VERSION 5.8 ;
DIVIDERCHAR "/" ;
BUSBITCHARS "[]" ;

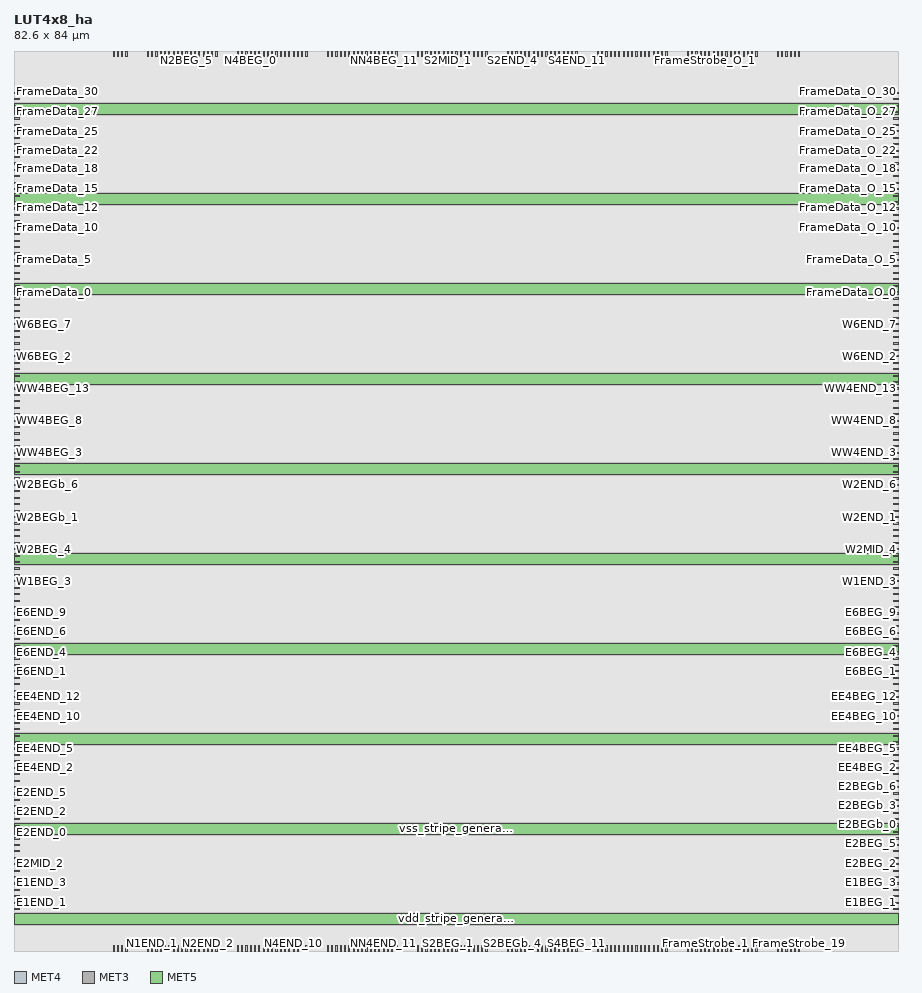
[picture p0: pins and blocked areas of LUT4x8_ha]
MACRO LUT4x8_ha
  CLASS BLOCK ;
  FOREIGN LUT4x8_ha ;
  ORIGIN 0.0 0.0 ;
  SIZE 82.600 BY 84.000 ;
  SYMMETRY X Y ;
  PIN N_GBUF_BEG_0
    DIRECTION OUTPUT ;
    USE SIGNAL ;
    PORT
      LAYER MET4 ;
        RECT 9.250 83.450 9.350 84.000 ;
    END
  END N_GBUF_BEG_0
  PIN N_GBUF_BEG_1
    DIRECTION OUTPUT ;
    USE SIGNAL ;
    PORT
      LAYER MET4 ;
        RECT 9.650 83.450 9.750 84.000 ;
    END
  END N_GBUF_BEG_1
  PIN N_GBUF_BEG_2
    DIRECTION OUTPUT ;
    USE SIGNAL ;
    PORT
      LAYER MET4 ;
        RECT 10.050 83.450 10.150 84.000 ;
    END
  END N_GBUF_BEG_2
  PIN N_GBUF_BEG_3
    DIRECTION OUTPUT ;
    USE SIGNAL ;
    PORT
      LAYER MET4 ;
        RECT 10.450 83.450 10.550 84.000 ;
    END
  END N_GBUF_BEG_3
  PIN N1BEG_0
    DIRECTION OUTPUT ;
    USE SIGNAL ;
    PORT
      LAYER MET4 ;
        RECT 12.450 83.450 12.550 84.000 ;
    END
  END N1BEG_0
  PIN N1BEG_1
    DIRECTION OUTPUT ;
    USE SIGNAL ;
    PORT
      LAYER MET4 ;
        RECT 12.850 83.450 12.950 84.000 ;
    END
  END N1BEG_1
  PIN N1BEG_2
    DIRECTION OUTPUT ;
    USE SIGNAL ;
    PORT
      LAYER MET4 ;
        RECT 13.250 83.450 13.350 84.000 ;
    END
  END N1BEG_2
  PIN N1BEG_3
    DIRECTION OUTPUT ;
    USE SIGNAL ;
    PORT
      LAYER MET4 ;
        RECT 13.650 83.450 13.750 84.000 ;
    END
  END N1BEG_3
  PIN N2BEG_0
    DIRECTION OUTPUT ;
    USE SIGNAL ;
    PORT
      LAYER MET4 ;
        RECT 14.050 83.450 14.150 84.000 ;
    END
  END N2BEG_0
  PIN N2BEG_1
    DIRECTION OUTPUT ;
    USE SIGNAL ;
    PORT
      LAYER MET4 ;
        RECT 14.450 83.450 14.550 84.000 ;
    END
  END N2BEG_1
  PIN N2BEG_2
    DIRECTION OUTPUT ;
    USE SIGNAL ;
    PORT
      LAYER MET4 ;
        RECT 14.850 83.450 14.950 84.000 ;
    END
  END N2BEG_2
  PIN N2BEG_3
    DIRECTION OUTPUT ;
    USE SIGNAL ;
    PORT
      LAYER MET4 ;
        RECT 15.250 83.450 15.350 84.000 ;
    END
  END N2BEG_3
  PIN N2BEG_4
    DIRECTION OUTPUT ;
    USE SIGNAL ;
    PORT
      LAYER MET4 ;
        RECT 15.650 83.450 15.750 84.000 ;
    END
  END N2BEG_4
  PIN N2BEG_5
    DIRECTION OUTPUT ;
    USE SIGNAL ;
    PORT
      LAYER MET4 ;
        RECT 16.050 83.450 16.150 84.000 ;
    END
  END N2BEG_5
  PIN N2BEG_6
    DIRECTION OUTPUT ;
    USE SIGNAL ;
    PORT
      LAYER MET4 ;
        RECT 16.450 83.450 16.550 84.000 ;
    END
  END N2BEG_6
  PIN N2BEG_7
    DIRECTION OUTPUT ;
    USE SIGNAL ;
    PORT
      LAYER MET4 ;
        RECT 16.850 83.450 16.950 84.000 ;
    END
  END N2BEG_7
  PIN N2BEGb_0
    DIRECTION OUTPUT ;
    USE SIGNAL ;
    PORT
      LAYER MET4 ;
        RECT 17.250 83.450 17.350 84.000 ;
    END
  END N2BEGb_0
  PIN N2BEGb_1
    DIRECTION OUTPUT ;
    USE SIGNAL ;
    PORT
      LAYER MET4 ;
        RECT 17.650 83.450 17.750 84.000 ;
    END
  END N2BEGb_1
  PIN N2BEGb_2
    DIRECTION OUTPUT ;
    USE SIGNAL ;
    PORT
      LAYER MET4 ;
        RECT 18.050 83.450 18.150 84.000 ;
    END
  END N2BEGb_2
  PIN N2BEGb_3
    DIRECTION OUTPUT ;
    USE SIGNAL ;
    PORT
      LAYER MET4 ;
        RECT 18.450 83.450 18.550 84.000 ;
    END
  END N2BEGb_3
  PIN N2BEGb_4
    DIRECTION OUTPUT ;
    USE SIGNAL ;
    PORT
      LAYER MET4 ;
        RECT 18.850 83.450 18.950 84.000 ;
    END
  END N2BEGb_4
  PIN N2BEGb_5
    DIRECTION OUTPUT ;
    USE SIGNAL ;
    PORT
      LAYER MET4 ;
        RECT 20.850 83.450 20.950 84.000 ;
    END
  END N2BEGb_5
  PIN N2BEGb_6
    DIRECTION OUTPUT ;
    USE SIGNAL ;
    PORT
      LAYER MET4 ;
        RECT 21.250 83.450 21.350 84.000 ;
    END
  END N2BEGb_6
  PIN N2BEGb_7
    DIRECTION OUTPUT ;
    USE SIGNAL ;
    PORT
      LAYER MET4 ;
        RECT 21.650 83.450 21.750 84.000 ;
    END
  END N2BEGb_7
  PIN N4BEG_0
    DIRECTION OUTPUT ;
    USE SIGNAL ;
    PORT
      LAYER MET4 ;
        RECT 22.050 83.450 22.150 84.000 ;
    END
  END N4BEG_0
  PIN N4BEG_1
    DIRECTION OUTPUT ;
    USE SIGNAL ;
    PORT
      LAYER MET4 ;
        RECT 22.450 83.450 22.550 84.000 ;
    END
  END N4BEG_1
  PIN N4BEG_2
    DIRECTION OUTPUT ;
    USE SIGNAL ;
    PORT
      LAYER MET4 ;
        RECT 22.850 83.450 22.950 84.000 ;
    END
  END N4BEG_2
  PIN N4BEG_3
    DIRECTION OUTPUT ;
    USE SIGNAL ;
    PORT
      LAYER MET4 ;
        RECT 23.250 83.450 23.350 84.000 ;
    END
  END N4BEG_3
  PIN N4BEG_4
    DIRECTION OUTPUT ;
    USE SIGNAL ;
    PORT
      LAYER MET4 ;
        RECT 23.650 83.450 23.750 84.000 ;
    END
  END N4BEG_4
  PIN N4BEG_5
    DIRECTION OUTPUT ;
    USE SIGNAL ;
    PORT
      LAYER MET4 ;
        RECT 24.050 83.450 24.150 84.000 ;
    END
  END N4BEG_5
  PIN N4BEG_6
    DIRECTION OUTPUT ;
    USE SIGNAL ;
    PORT
      LAYER MET4 ;
        RECT 24.450 83.450 24.550 84.000 ;
    END
  END N4BEG_6
  PIN N4BEG_7
    DIRECTION OUTPUT ;
    USE SIGNAL ;
    PORT
      LAYER MET4 ;
        RECT 24.850 83.450 24.950 84.000 ;
    END
  END N4BEG_7
  PIN N4BEG_8
    DIRECTION OUTPUT ;
    USE SIGNAL ;
    PORT
      LAYER MET4 ;
        RECT 25.250 83.450 25.350 84.000 ;
    END
  END N4BEG_8
  PIN N4BEG_9
    DIRECTION OUTPUT ;
    USE SIGNAL ;
    PORT
      LAYER MET4 ;
        RECT 25.650 83.450 25.750 84.000 ;
    END
  END N4BEG_9
  PIN N4BEG_10
    DIRECTION OUTPUT ;
    USE SIGNAL ;
    PORT
      LAYER MET4 ;
        RECT 26.050 83.450 26.150 84.000 ;
    END
  END N4BEG_10
  PIN N4BEG_11
    DIRECTION OUTPUT ;
    USE SIGNAL ;
    PORT
      LAYER MET4 ;
        RECT 26.450 83.450 26.550 84.000 ;
    END
  END N4BEG_11
  PIN N4BEG_12
    DIRECTION OUTPUT ;
    USE SIGNAL ;
    PORT
      LAYER MET4 ;
        RECT 26.850 83.450 26.950 84.000 ;
    END
  END N4BEG_12
  PIN N4BEG_13
    DIRECTION OUTPUT ;
    USE SIGNAL ;
    PORT
      LAYER MET4 ;
        RECT 27.250 83.450 27.350 84.000 ;
    END
  END N4BEG_13
  PIN N4BEG_14
    DIRECTION OUTPUT ;
    USE SIGNAL ;
    PORT
      LAYER MET4 ;
        RECT 29.250 83.450 29.350 84.000 ;
    END
  END N4BEG_14
  PIN N4BEG_15
    DIRECTION OUTPUT ;
    USE SIGNAL ;
    PORT
      LAYER MET4 ;
        RECT 29.650 83.450 29.750 84.000 ;
    END
  END N4BEG_15
  PIN NN4BEG_0
    DIRECTION OUTPUT ;
    USE SIGNAL ;
    PORT
      LAYER MET4 ;
        RECT 30.050 83.450 30.150 84.000 ;
    END
  END NN4BEG_0
  PIN NN4BEG_1
    DIRECTION OUTPUT ;
    USE SIGNAL ;
    PORT
      LAYER MET4 ;
        RECT 30.450 83.450 30.550 84.000 ;
    END
  END NN4BEG_1
  PIN NN4BEG_2
    DIRECTION OUTPUT ;
    USE SIGNAL ;
    PORT
      LAYER MET4 ;
        RECT 30.850 83.450 30.950 84.000 ;
    END
  END NN4BEG_2
  PIN NN4BEG_3
    DIRECTION OUTPUT ;
    USE SIGNAL ;
    PORT
      LAYER MET4 ;
        RECT 31.250 83.450 31.350 84.000 ;
    END
  END NN4BEG_3
  PIN NN4BEG_4
    DIRECTION OUTPUT ;
    USE SIGNAL ;
    PORT
      LAYER MET4 ;
        RECT 31.650 83.450 31.750 84.000 ;
    END
  END NN4BEG_4
  PIN NN4BEG_5
    DIRECTION OUTPUT ;
    USE SIGNAL ;
    PORT
      LAYER MET4 ;
        RECT 32.050 83.450 32.150 84.000 ;
    END
  END NN4BEG_5
  PIN NN4BEG_6
    DIRECTION OUTPUT ;
    USE SIGNAL ;
    PORT
      LAYER MET4 ;
        RECT 32.450 83.450 32.550 84.000 ;
    END
  END NN4BEG_6
  PIN NN4BEG_7
    DIRECTION OUTPUT ;
    USE SIGNAL ;
    PORT
      LAYER MET4 ;
        RECT 32.850 83.450 32.950 84.000 ;
    END
  END NN4BEG_7
  PIN NN4BEG_8
    DIRECTION OUTPUT ;
    USE SIGNAL ;
    PORT
      LAYER MET4 ;
        RECT 33.250 83.450 33.350 84.000 ;
    END
  END NN4BEG_8
  PIN NN4BEG_9
    DIRECTION OUTPUT ;
    USE SIGNAL ;
    PORT
      LAYER MET4 ;
        RECT 33.650 83.450 33.750 84.000 ;
    END
  END NN4BEG_9
  PIN NN4BEG_10
    DIRECTION OUTPUT ;
    USE SIGNAL ;
    PORT
      LAYER MET4 ;
        RECT 34.050 83.450 34.150 84.000 ;
    END
  END NN4BEG_10
  PIN NN4BEG_11
    DIRECTION OUTPUT ;
    USE SIGNAL ;
    PORT
      LAYER MET4 ;
        RECT 34.450 83.450 34.550 84.000 ;
    END
  END NN4BEG_11
  PIN NN4BEG_12
    DIRECTION OUTPUT ;
    USE SIGNAL ;
    PORT
      LAYER MET4 ;
        RECT 34.850 83.450 34.950 84.000 ;
    END
  END NN4BEG_12
  PIN NN4BEG_13
    DIRECTION OUTPUT ;
    USE SIGNAL ;
    PORT
      LAYER MET4 ;
        RECT 35.250 83.450 35.350 84.000 ;
    END
  END NN4BEG_13
  PIN NN4BEG_14
    DIRECTION OUTPUT ;
    USE SIGNAL ;
    PORT
      LAYER MET4 ;
        RECT 35.650 83.450 35.750 84.000 ;
    END
  END NN4BEG_14
  PIN NN4BEG_15
    DIRECTION OUTPUT ;
    USE SIGNAL ;
    PORT
      LAYER MET4 ;
        RECT 37.650 83.450 37.750 84.000 ;
    END
  END NN4BEG_15
  PIN S1END_0
    DIRECTION INPUT ;
    USE SIGNAL ;
    PORT
      LAYER MET4 ;
        RECT 38.450 83.450 38.550 84.000 ;
    END
  END S1END_0
  PIN S1END_1
    DIRECTION INPUT ;
    USE SIGNAL ;
    PORT
      LAYER MET4 ;
        RECT 38.850 83.450 38.950 84.000 ;
    END
  END S1END_1
  PIN S1END_2
    DIRECTION INPUT ;
    USE SIGNAL ;
    PORT
      LAYER MET4 ;
        RECT 39.250 83.450 39.350 84.000 ;
    END
  END S1END_2
  PIN S1END_3
    DIRECTION INPUT ;
    USE SIGNAL ;
    PORT
      LAYER MET4 ;
        RECT 39.650 83.450 39.750 84.000 ;
    END
  END S1END_3
  PIN S2MID_0
    DIRECTION INPUT ;
    USE SIGNAL ;
    PORT
      LAYER MET4 ;
        RECT 40.050 83.450 40.150 84.000 ;
    END
  END S2MID_0
  PIN S2MID_1
    DIRECTION INPUT ;
    USE SIGNAL ;
    PORT
      LAYER MET4 ;
        RECT 40.450 83.450 40.550 84.000 ;
    END
  END S2MID_1
  PIN S2MID_2
    DIRECTION INPUT ;
    USE SIGNAL ;
    PORT
      LAYER MET4 ;
        RECT 40.850 83.450 40.950 84.000 ;
    END
  END S2MID_2
  PIN S2MID_3
    DIRECTION INPUT ;
    USE SIGNAL ;
    PORT
      LAYER MET4 ;
        RECT 41.250 83.450 41.350 84.000 ;
    END
  END S2MID_3
  PIN S2MID_4
    DIRECTION INPUT ;
    USE SIGNAL ;
    PORT
      LAYER MET4 ;
        RECT 41.650 83.450 41.750 84.000 ;
    END
  END S2MID_4
  PIN S2MID_5
    DIRECTION INPUT ;
    USE SIGNAL ;
    PORT
      LAYER MET4 ;
        RECT 42.050 83.450 42.150 84.000 ;
    END
  END S2MID_5
  PIN S2MID_6
    DIRECTION INPUT ;
    USE SIGNAL ;
    PORT
      LAYER MET4 ;
        RECT 42.450 83.450 42.550 84.000 ;
    END
  END S2MID_6
  PIN S2MID_7
    DIRECTION INPUT ;
    USE SIGNAL ;
    PORT
      LAYER MET4 ;
        RECT 42.850 83.450 42.950 84.000 ;
    END
  END S2MID_7
  PIN S2END_0
    DIRECTION INPUT ;
    USE SIGNAL ;
    PORT
      LAYER MET4 ;
        RECT 43.250 83.450 43.350 84.000 ;
    END
  END S2END_0
  PIN S2END_1
    DIRECTION INPUT ;
    USE SIGNAL ;
    PORT
      LAYER MET4 ;
        RECT 43.650 83.450 43.750 84.000 ;
    END
  END S2END_1
  PIN S2END_2
    DIRECTION INPUT ;
    USE SIGNAL ;
    PORT
      LAYER MET4 ;
        RECT 44.050 83.450 44.150 84.000 ;
    END
  END S2END_2
  PIN S2END_3
    DIRECTION INPUT ;
    USE SIGNAL ;
    PORT
      LAYER MET4 ;
        RECT 46.050 83.450 46.150 84.000 ;
    END
  END S2END_3
  PIN S2END_4
    DIRECTION INPUT ;
    USE SIGNAL ;
    PORT
      LAYER MET4 ;
        RECT 46.450 83.450 46.550 84.000 ;
    END
  END S2END_4
  PIN S2END_5
    DIRECTION INPUT ;
    USE SIGNAL ;
    PORT
      LAYER MET4 ;
        RECT 46.850 83.450 46.950 84.000 ;
    END
  END S2END_5
  PIN S2END_6
    DIRECTION INPUT ;
    USE SIGNAL ;
    PORT
      LAYER MET4 ;
        RECT 47.250 83.450 47.350 84.000 ;
    END
  END S2END_6
  PIN S2END_7
    DIRECTION INPUT ;
    USE SIGNAL ;
    PORT
      LAYER MET4 ;
        RECT 47.650 83.450 47.750 84.000 ;
    END
  END S2END_7
  PIN S4END_0
    DIRECTION INPUT ;
    USE SIGNAL ;
    PORT
      LAYER MET4 ;
        RECT 48.050 83.450 48.150 84.000 ;
    END
  END S4END_0
  PIN S4END_1
    DIRECTION INPUT ;
    USE SIGNAL ;
    PORT
      LAYER MET4 ;
        RECT 48.450 83.450 48.550 84.000 ;
    END
  END S4END_1
  PIN S4END_2
    DIRECTION INPUT ;
    USE SIGNAL ;
    PORT
      LAYER MET4 ;
        RECT 48.850 83.450 48.950 84.000 ;
    END
  END S4END_2
  PIN S4END_3
    DIRECTION INPUT ;
    USE SIGNAL ;
    PORT
      LAYER MET4 ;
        RECT 49.250 83.450 49.350 84.000 ;
    END
  END S4END_3
  PIN S4END_4
    DIRECTION INPUT ;
    USE SIGNAL ;
    PORT
      LAYER MET4 ;
        RECT 49.650 83.450 49.750 84.000 ;
    END
  END S4END_4
  PIN S4END_5
    DIRECTION INPUT ;
    USE SIGNAL ;
    PORT
      LAYER MET4 ;
        RECT 50.050 83.450 50.150 84.000 ;
    END
  END S4END_5
  PIN S4END_6
    DIRECTION INPUT ;
    USE SIGNAL ;
    PORT
      LAYER MET4 ;
        RECT 50.450 83.450 50.550 84.000 ;
    END
  END S4END_6
  PIN S4END_7
    DIRECTION INPUT ;
    USE SIGNAL ;
    PORT
      LAYER MET4 ;
        RECT 50.850 83.450 50.950 84.000 ;
    END
  END S4END_7
  PIN S4END_8
    DIRECTION INPUT ;
    USE SIGNAL ;
    PORT
      LAYER MET4 ;
        RECT 51.250 83.450 51.350 84.000 ;
    END
  END S4END_8
  PIN S4END_9
    DIRECTION INPUT ;
    USE SIGNAL ;
    PORT
      LAYER MET4 ;
        RECT 51.650 83.450 51.750 84.000 ;
    END
  END S4END_9
  PIN S4END_10
    DIRECTION INPUT ;
    USE SIGNAL ;
    PORT
      LAYER MET4 ;
        RECT 52.050 83.450 52.150 84.000 ;
    END
  END S4END_10
  PIN S4END_11
    DIRECTION INPUT ;
    USE SIGNAL ;
    PORT
      LAYER MET4 ;
        RECT 52.450 83.450 52.550 84.000 ;
    END
  END S4END_11
  PIN S4END_12
    DIRECTION INPUT ;
    USE SIGNAL ;
    PORT
      LAYER MET4 ;
        RECT 54.450 83.450 54.550 84.000 ;
    END
  END S4END_12
  PIN S4END_13
    DIRECTION INPUT ;
    USE SIGNAL ;
    PORT
      LAYER MET4 ;
        RECT 54.850 83.450 54.950 84.000 ;
    END
  END S4END_13
  PIN S4END_14
    DIRECTION INPUT ;
    USE SIGNAL ;
    PORT
      LAYER MET4 ;
        RECT 55.250 83.450 55.350 84.000 ;
    END
  END S4END_14
  PIN S4END_15
    DIRECTION INPUT ;
    USE SIGNAL ;
    PORT
      LAYER MET4 ;
        RECT 55.650 83.450 55.750 84.000 ;
    END
  END S4END_15
  PIN SS4END_0
    DIRECTION INPUT ;
    USE SIGNAL ;
    PORT
      LAYER MET4 ;
        RECT 56.050 83.450 56.150 84.000 ;
    END
  END SS4END_0
  PIN SS4END_1
    DIRECTION INPUT ;
    USE SIGNAL ;
    PORT
      LAYER MET4 ;
        RECT 56.450 83.450 56.550 84.000 ;
    END
  END SS4END_1
  PIN SS4END_2
    DIRECTION INPUT ;
    USE SIGNAL ;
    PORT
      LAYER MET4 ;
        RECT 56.850 83.450 56.950 84.000 ;
    END
  END SS4END_2
  PIN SS4END_3
    DIRECTION INPUT ;
    USE SIGNAL ;
    PORT
      LAYER MET4 ;
        RECT 57.250 83.450 57.350 84.000 ;
    END
  END SS4END_3
  PIN SS4END_4
    DIRECTION INPUT ;
    USE SIGNAL ;
    PORT
      LAYER MET4 ;
        RECT 57.650 83.450 57.750 84.000 ;
    END
  END SS4END_4
  PIN SS4END_5
    DIRECTION INPUT ;
    USE SIGNAL ;
    PORT
      LAYER MET4 ;
        RECT 58.050 83.450 58.150 84.000 ;
    END
  END SS4END_5
  PIN SS4END_6
    DIRECTION INPUT ;
    USE SIGNAL ;
    PORT
      LAYER MET4 ;
        RECT 58.450 83.450 58.550 84.000 ;
    END
  END SS4END_6
  PIN SS4END_7
    DIRECTION INPUT ;
    USE SIGNAL ;
    PORT
      LAYER MET4 ;
        RECT 58.850 83.450 58.950 84.000 ;
    END
  END SS4END_7
  PIN SS4END_8
    DIRECTION INPUT ;
    USE SIGNAL ;
    PORT
      LAYER MET4 ;
        RECT 59.250 83.450 59.350 84.000 ;
    END
  END SS4END_8
  PIN SS4END_9
    DIRECTION INPUT ;
    USE SIGNAL ;
    PORT
      LAYER MET4 ;
        RECT 59.650 83.450 59.750 84.000 ;
    END
  END SS4END_9
  PIN SS4END_10
    DIRECTION INPUT ;
    USE SIGNAL ;
    PORT
      LAYER MET4 ;
        RECT 60.050 83.450 60.150 84.000 ;
    END
  END SS4END_10
  PIN SS4END_11
    DIRECTION INPUT ;
    USE SIGNAL ;
    PORT
      LAYER MET4 ;
        RECT 60.450 83.450 60.550 84.000 ;
    END
  END SS4END_11
  PIN SS4END_12
    DIRECTION INPUT ;
    USE SIGNAL ;
    PORT
      LAYER MET4 ;
        RECT 60.850 83.450 60.950 84.000 ;
    END
  END SS4END_12
  PIN SS4END_13
    DIRECTION INPUT ;
    USE SIGNAL ;
    PORT
      LAYER MET4 ;
        RECT 62.850 83.450 62.950 84.000 ;
    END
  END SS4END_13
  PIN SS4END_14
    DIRECTION INPUT ;
    USE SIGNAL ;
    PORT
      LAYER MET4 ;
        RECT 63.250 83.450 63.350 84.000 ;
    END
  END SS4END_14
  PIN SS4END_15
    DIRECTION INPUT ;
    USE SIGNAL ;
    PORT
      LAYER MET4 ;
        RECT 63.650 83.450 63.750 84.000 ;
    END
  END SS4END_15
  PIN CO_0
    DIRECTION OUTPUT ;
    USE SIGNAL ;
    PORT
      LAYER MET4 ;
        RECT 38.050 83.450 38.150 84.000 ;
    END
  END CO_0
  PIN E1BEG_0
    DIRECTION OUTPUT ;
    USE SIGNAL ;
    PORT
      LAYER MET3 ;
        RECT 82.050 3.850 82.600 3.950 ;
    END
  END E1BEG_0
  PIN E1BEG_1
    DIRECTION OUTPUT ;
    USE SIGNAL ;
    PORT
      LAYER MET3 ;
        RECT 82.050 4.450 82.600 4.550 ;
    END
  END E1BEG_1
  PIN E1BEG_2
    DIRECTION OUTPUT ;
    USE SIGNAL ;
    PORT
      LAYER MET3 ;
        RECT 82.050 5.050 82.600 5.150 ;
    END
  END E1BEG_2
  PIN E1BEG_3
    DIRECTION OUTPUT ;
    USE SIGNAL ;
    PORT
      LAYER MET3 ;
        RECT 82.050 5.650 82.600 5.750 ;
    END
  END E1BEG_3
  PIN E2BEG_0
    DIRECTION OUTPUT ;
    USE SIGNAL ;
    PORT
      LAYER MET3 ;
        RECT 82.050 6.250 82.600 6.350 ;
    END
  END E2BEG_0
  PIN E2BEG_1
    DIRECTION OUTPUT ;
    USE SIGNAL ;
    PORT
      LAYER MET3 ;
        RECT 82.050 6.850 82.600 6.950 ;
    END
  END E2BEG_1
  PIN E2BEG_2
    DIRECTION OUTPUT ;
    USE SIGNAL ;
    PORT
      LAYER MET3 ;
        RECT 82.050 7.450 82.600 7.550 ;
    END
  END E2BEG_2
  PIN E2BEG_3
    DIRECTION OUTPUT ;
    USE SIGNAL ;
    PORT
      LAYER MET3 ;
        RECT 82.050 8.050 82.600 8.150 ;
    END
  END E2BEG_3
  PIN E2BEG_4
    DIRECTION OUTPUT ;
    USE SIGNAL ;
    PORT
      LAYER MET3 ;
        RECT 82.050 8.650 82.600 8.750 ;
    END
  END E2BEG_4
  PIN E2BEG_5
    DIRECTION OUTPUT ;
    USE SIGNAL ;
    PORT
      LAYER MET3 ;
        RECT 82.050 9.250 82.600 9.350 ;
    END
  END E2BEG_5
  PIN E2BEG_6
    DIRECTION OUTPUT ;
    USE SIGNAL ;
    PORT
      LAYER MET3 ;
        RECT 82.050 9.850 82.600 9.950 ;
    END
  END E2BEG_6
  PIN E2BEG_7
    DIRECTION OUTPUT ;
    USE SIGNAL ;
    PORT
      LAYER MET3 ;
        RECT 82.050 10.450 82.600 10.550 ;
    END
  END E2BEG_7
  PIN E2BEGb_0
    DIRECTION OUTPUT ;
    USE SIGNAL ;
    PORT
      LAYER MET3 ;
        RECT 82.050 11.050 82.600 11.150 ;
    END
  END E2BEGb_0
  PIN E2BEGb_1
    DIRECTION OUTPUT ;
    USE SIGNAL ;
    PORT
      LAYER MET3 ;
        RECT 82.050 11.650 82.600 11.750 ;
    END
  END E2BEGb_1
  PIN E2BEGb_2
    DIRECTION OUTPUT ;
    USE SIGNAL ;
    PORT
      LAYER MET3 ;
        RECT 82.050 12.250 82.600 12.350 ;
    END
  END E2BEGb_2
  PIN E2BEGb_3
    DIRECTION OUTPUT ;
    USE SIGNAL ;
    PORT
      LAYER MET3 ;
        RECT 82.050 12.850 82.600 12.950 ;
    END
  END E2BEGb_3
  PIN E2BEGb_4
    DIRECTION OUTPUT ;
    USE SIGNAL ;
    PORT
      LAYER MET3 ;
        RECT 82.050 13.450 82.600 13.550 ;
    END
  END E2BEGb_4
  PIN E2BEGb_5
    DIRECTION OUTPUT ;
    USE SIGNAL ;
    PORT
      LAYER MET3 ;
        RECT 82.050 14.050 82.600 14.150 ;
    END
  END E2BEGb_5
  PIN E2BEGb_6
    DIRECTION OUTPUT ;
    USE SIGNAL ;
    PORT
      LAYER MET3 ;
        RECT 82.050 14.650 82.600 14.750 ;
    END
  END E2BEGb_6
  PIN E2BEGb_7
    DIRECTION OUTPUT ;
    USE SIGNAL ;
    PORT
      LAYER MET3 ;
        RECT 82.050 15.250 82.600 15.350 ;
    END
  END E2BEGb_7
  PIN EE4BEG_0
    DIRECTION OUTPUT ;
    USE SIGNAL ;
    PORT
      LAYER MET3 ;
        RECT 82.050 15.850 82.600 15.950 ;
    END
  END EE4BEG_0
  PIN EE4BEG_1
    DIRECTION OUTPUT ;
    USE SIGNAL ;
    PORT
      LAYER MET3 ;
        RECT 82.050 16.450 82.600 16.550 ;
    END
  END EE4BEG_1
  PIN EE4BEG_2
    DIRECTION OUTPUT ;
    USE SIGNAL ;
    PORT
      LAYER MET3 ;
        RECT 82.050 17.050 82.600 17.150 ;
    END
  END EE4BEG_2
  PIN EE4BEG_3
    DIRECTION OUTPUT ;
    USE SIGNAL ;
    PORT
      LAYER MET3 ;
        RECT 82.050 17.650 82.600 17.750 ;
    END
  END EE4BEG_3
  PIN EE4BEG_4
    DIRECTION OUTPUT ;
    USE SIGNAL ;
    PORT
      LAYER MET3 ;
        RECT 82.050 18.250 82.600 18.350 ;
    END
  END EE4BEG_4
  PIN EE4BEG_5
    DIRECTION OUTPUT ;
    USE SIGNAL ;
    PORT
      LAYER MET3 ;
        RECT 82.050 18.850 82.600 18.950 ;
    END
  END EE4BEG_5
  PIN EE4BEG_6
    DIRECTION OUTPUT ;
    USE SIGNAL ;
    PORT
      LAYER MET3 ;
        RECT 82.050 19.450 82.600 19.550 ;
    END
  END EE4BEG_6
  PIN EE4BEG_7
    DIRECTION OUTPUT ;
    USE SIGNAL ;
    PORT
      LAYER MET3 ;
        RECT 82.050 20.050 82.600 20.150 ;
    END
  END EE4BEG_7
  PIN EE4BEG_8
    DIRECTION OUTPUT ;
    USE SIGNAL ;
    PORT
      LAYER MET3 ;
        RECT 82.050 20.650 82.600 20.750 ;
    END
  END EE4BEG_8
  PIN EE4BEG_9
    DIRECTION OUTPUT ;
    USE SIGNAL ;
    PORT
      LAYER MET3 ;
        RECT 82.050 21.250 82.600 21.350 ;
    END
  END EE4BEG_9
  PIN EE4BEG_10
    DIRECTION OUTPUT ;
    USE SIGNAL ;
    PORT
      LAYER MET3 ;
        RECT 82.050 21.850 82.600 21.950 ;
    END
  END EE4BEG_10
  PIN EE4BEG_11
    DIRECTION OUTPUT ;
    USE SIGNAL ;
    PORT
      LAYER MET3 ;
        RECT 82.050 22.450 82.600 22.550 ;
    END
  END EE4BEG_11
  PIN EE4BEG_12
    DIRECTION OUTPUT ;
    USE SIGNAL ;
    PORT
      LAYER MET3 ;
        RECT 82.050 23.050 82.600 23.150 ;
    END
  END EE4BEG_12
  PIN EE4BEG_13
    DIRECTION OUTPUT ;
    USE SIGNAL ;
    PORT
      LAYER MET3 ;
        RECT 82.050 23.650 82.600 23.750 ;
    END
  END EE4BEG_13
  PIN EE4BEG_14
    DIRECTION OUTPUT ;
    USE SIGNAL ;
    PORT
      LAYER MET3 ;
        RECT 82.050 24.250 82.600 24.350 ;
    END
  END EE4BEG_14
  PIN EE4BEG_15
    DIRECTION OUTPUT ;
    USE SIGNAL ;
    PORT
      LAYER MET3 ;
        RECT 82.050 24.850 82.600 24.950 ;
    END
  END EE4BEG_15
  PIN E6BEG_0
    DIRECTION OUTPUT ;
    USE SIGNAL ;
    PORT
      LAYER MET3 ;
        RECT 82.050 25.450 82.600 25.550 ;
    END
  END E6BEG_0
  PIN E6BEG_1
    DIRECTION OUTPUT ;
    USE SIGNAL ;
    PORT
      LAYER MET3 ;
        RECT 82.050 26.050 82.600 26.150 ;
    END
  END E6BEG_1
  PIN E6BEG_2
    DIRECTION OUTPUT ;
    USE SIGNAL ;
    PORT
      LAYER MET3 ;
        RECT 82.050 26.650 82.600 26.750 ;
    END
  END E6BEG_2
  PIN E6BEG_3
    DIRECTION OUTPUT ;
    USE SIGNAL ;
    PORT
      LAYER MET3 ;
        RECT 82.050 27.250 82.600 27.350 ;
    END
  END E6BEG_3
  PIN E6BEG_4
    DIRECTION OUTPUT ;
    USE SIGNAL ;
    PORT
      LAYER MET3 ;
        RECT 82.050 27.850 82.600 27.950 ;
    END
  END E6BEG_4
  PIN E6BEG_5
    DIRECTION OUTPUT ;
    USE SIGNAL ;
    PORT
      LAYER MET3 ;
        RECT 82.050 28.450 82.600 28.550 ;
    END
  END E6BEG_5
  PIN E6BEG_6
    DIRECTION OUTPUT ;
    USE SIGNAL ;
    PORT
      LAYER MET3 ;
        RECT 82.050 29.050 82.600 29.150 ;
    END
  END E6BEG_6
  PIN E6BEG_7
    DIRECTION OUTPUT ;
    USE SIGNAL ;
    PORT
      LAYER MET3 ;
        RECT 82.050 29.650 82.600 29.750 ;
    END
  END E6BEG_7
  PIN E6BEG_8
    DIRECTION OUTPUT ;
    USE SIGNAL ;
    PORT
      LAYER MET3 ;
        RECT 82.050 30.250 82.600 30.350 ;
    END
  END E6BEG_8
  PIN E6BEG_9
    DIRECTION OUTPUT ;
    USE SIGNAL ;
    PORT
      LAYER MET3 ;
        RECT 82.050 30.850 82.600 30.950 ;
    END
  END E6BEG_9
  PIN E6BEG_10
    DIRECTION OUTPUT ;
    USE SIGNAL ;
    PORT
      LAYER MET3 ;
        RECT 82.050 31.450 82.600 31.550 ;
    END
  END E6BEG_10
  PIN E6BEG_11
    DIRECTION OUTPUT ;
    USE SIGNAL ;
    PORT
      LAYER MET3 ;
        RECT 82.050 32.050 82.600 32.150 ;
    END
  END E6BEG_11
  PIN W1END_0
    DIRECTION INPUT ;
    USE SIGNAL ;
    PORT
      LAYER MET3 ;
        RECT 82.050 32.650 82.600 32.750 ;
    END
  END W1END_0
  PIN W1END_1
    DIRECTION INPUT ;
    USE SIGNAL ;
    PORT
      LAYER MET3 ;
        RECT 82.050 33.250 82.600 33.350 ;
    END
  END W1END_1
  PIN W1END_2
    DIRECTION INPUT ;
    USE SIGNAL ;
    PORT
      LAYER MET3 ;
        RECT 82.050 33.850 82.600 33.950 ;
    END
  END W1END_2
  PIN W1END_3
    DIRECTION INPUT ;
    USE SIGNAL ;
    PORT
      LAYER MET3 ;
        RECT 82.050 34.450 82.600 34.550 ;
    END
  END W1END_3
  PIN W2MID_0
    DIRECTION INPUT ;
    USE SIGNAL ;
    PORT
      LAYER MET3 ;
        RECT 82.050 35.050 82.600 35.150 ;
    END
  END W2MID_0
  PIN W2MID_1
    DIRECTION INPUT ;
    USE SIGNAL ;
    PORT
      LAYER MET3 ;
        RECT 82.050 35.650 82.600 35.750 ;
    END
  END W2MID_1
  PIN W2MID_2
    DIRECTION INPUT ;
    USE SIGNAL ;
    PORT
      LAYER MET3 ;
        RECT 82.050 36.250 82.600 36.350 ;
    END
  END W2MID_2
  PIN W2MID_3
    DIRECTION INPUT ;
    USE SIGNAL ;
    PORT
      LAYER MET3 ;
        RECT 82.050 36.850 82.600 36.950 ;
    END
  END W2MID_3
  PIN W2MID_4
    DIRECTION INPUT ;
    USE SIGNAL ;
    PORT
      LAYER MET3 ;
        RECT 82.050 37.450 82.600 37.550 ;
    END
  END W2MID_4
  PIN W2MID_5
    DIRECTION INPUT ;
    USE SIGNAL ;
    PORT
      LAYER MET3 ;
        RECT 82.050 38.050 82.600 38.150 ;
    END
  END W2MID_5
  PIN W2MID_6
    DIRECTION INPUT ;
    USE SIGNAL ;
    PORT
      LAYER MET3 ;
        RECT 82.050 38.650 82.600 38.750 ;
    END
  END W2MID_6
  PIN W2MID_7
    DIRECTION INPUT ;
    USE SIGNAL ;
    PORT
      LAYER MET3 ;
        RECT 82.050 39.250 82.600 39.350 ;
    END
  END W2MID_7
  PIN W2END_0
    DIRECTION INPUT ;
    USE SIGNAL ;
    PORT
      LAYER MET3 ;
        RECT 82.050 39.850 82.600 39.950 ;
    END
  END W2END_0
  PIN W2END_1
    DIRECTION INPUT ;
    USE SIGNAL ;
    PORT
      LAYER MET3 ;
        RECT 82.050 40.450 82.600 40.550 ;
    END
  END W2END_1
  PIN W2END_2
    DIRECTION INPUT ;
    USE SIGNAL ;
    PORT
      LAYER MET3 ;
        RECT 82.050 41.050 82.600 41.150 ;
    END
  END W2END_2
  PIN W2END_3
    DIRECTION INPUT ;
    USE SIGNAL ;
    PORT
      LAYER MET3 ;
        RECT 82.050 41.650 82.600 41.750 ;
    END
  END W2END_3
  PIN W2END_4
    DIRECTION INPUT ;
    USE SIGNAL ;
    PORT
      LAYER MET3 ;
        RECT 82.050 42.250 82.600 42.350 ;
    END
  END W2END_4
  PIN W2END_5
    DIRECTION INPUT ;
    USE SIGNAL ;
    PORT
      LAYER MET3 ;
        RECT 82.050 42.850 82.600 42.950 ;
    END
  END W2END_5
  PIN W2END_6
    DIRECTION INPUT ;
    USE SIGNAL ;
    PORT
      LAYER MET3 ;
        RECT 82.050 43.450 82.600 43.550 ;
    END
  END W2END_6
  PIN W2END_7
    DIRECTION INPUT ;
    USE SIGNAL ;
    PORT
      LAYER MET3 ;
        RECT 82.050 44.050 82.600 44.150 ;
    END
  END W2END_7
  PIN WW4END_0
    DIRECTION INPUT ;
    USE SIGNAL ;
    PORT
      LAYER MET3 ;
        RECT 82.050 44.650 82.600 44.750 ;
    END
  END WW4END_0
  PIN WW4END_1
    DIRECTION INPUT ;
    USE SIGNAL ;
    PORT
      LAYER MET3 ;
        RECT 82.050 45.250 82.600 45.350 ;
    END
  END WW4END_1
  PIN WW4END_2
    DIRECTION INPUT ;
    USE SIGNAL ;
    PORT
      LAYER MET3 ;
        RECT 82.050 45.850 82.600 45.950 ;
    END
  END WW4END_2
  PIN WW4END_3
    DIRECTION INPUT ;
    USE SIGNAL ;
    PORT
      LAYER MET3 ;
        RECT 82.050 46.450 82.600 46.550 ;
    END
  END WW4END_3
  PIN WW4END_4
    DIRECTION INPUT ;
    USE SIGNAL ;
    PORT
      LAYER MET3 ;
        RECT 82.050 47.050 82.600 47.150 ;
    END
  END WW4END_4
  PIN WW4END_5
    DIRECTION INPUT ;
    USE SIGNAL ;
    PORT
      LAYER MET3 ;
        RECT 82.050 47.650 82.600 47.750 ;
    END
  END WW4END_5
  PIN WW4END_6
    DIRECTION INPUT ;
    USE SIGNAL ;
    PORT
      LAYER MET3 ;
        RECT 82.050 48.250 82.600 48.350 ;
    END
  END WW4END_6
  PIN WW4END_7
    DIRECTION INPUT ;
    USE SIGNAL ;
    PORT
      LAYER MET3 ;
        RECT 82.050 48.850 82.600 48.950 ;
    END
  END WW4END_7
  PIN WW4END_8
    DIRECTION INPUT ;
    USE SIGNAL ;
    PORT
      LAYER MET3 ;
        RECT 82.050 49.450 82.600 49.550 ;
    END
  END WW4END_8
  PIN WW4END_9
    DIRECTION INPUT ;
    USE SIGNAL ;
    PORT
      LAYER MET3 ;
        RECT 82.050 50.050 82.600 50.150 ;
    END
  END WW4END_9
  PIN WW4END_10
    DIRECTION INPUT ;
    USE SIGNAL ;
    PORT
      LAYER MET3 ;
        RECT 82.050 50.650 82.600 50.750 ;
    END
  END WW4END_10
  PIN WW4END_11
    DIRECTION INPUT ;
    USE SIGNAL ;
    PORT
      LAYER MET3 ;
        RECT 82.050 51.250 82.600 51.350 ;
    END
  END WW4END_11
  PIN WW4END_12
    DIRECTION INPUT ;
    USE SIGNAL ;
    PORT
      LAYER MET3 ;
        RECT 82.050 51.850 82.600 51.950 ;
    END
  END WW4END_12
  PIN WW4END_13
    DIRECTION INPUT ;
    USE SIGNAL ;
    PORT
      LAYER MET3 ;
        RECT 82.050 52.450 82.600 52.550 ;
    END
  END WW4END_13
  PIN WW4END_14
    DIRECTION INPUT ;
    USE SIGNAL ;
    PORT
      LAYER MET3 ;
        RECT 82.050 53.050 82.600 53.150 ;
    END
  END WW4END_14
  PIN WW4END_15
    DIRECTION INPUT ;
    USE SIGNAL ;
    PORT
      LAYER MET3 ;
        RECT 82.050 53.650 82.600 53.750 ;
    END
  END WW4END_15
  PIN W6END_0
    DIRECTION INPUT ;
    USE SIGNAL ;
    PORT
      LAYER MET3 ;
        RECT 82.050 54.250 82.600 54.350 ;
    END
  END W6END_0
  PIN W6END_1
    DIRECTION INPUT ;
    USE SIGNAL ;
    PORT
      LAYER MET3 ;
        RECT 82.050 54.850 82.600 54.950 ;
    END
  END W6END_1
  PIN W6END_2
    DIRECTION INPUT ;
    USE SIGNAL ;
    PORT
      LAYER MET3 ;
        RECT 82.050 55.450 82.600 55.550 ;
    END
  END W6END_2
  PIN W6END_3
    DIRECTION INPUT ;
    USE SIGNAL ;
    PORT
      LAYER MET3 ;
        RECT 82.050 56.050 82.600 56.150 ;
    END
  END W6END_3
  PIN W6END_4
    DIRECTION INPUT ;
    USE SIGNAL ;
    PORT
      LAYER MET3 ;
        RECT 82.050 56.650 82.600 56.750 ;
    END
  END W6END_4
  PIN W6END_5
    DIRECTION INPUT ;
    USE SIGNAL ;
    PORT
      LAYER MET3 ;
        RECT 82.050 57.250 82.600 57.350 ;
    END
  END W6END_5
  PIN W6END_6
    DIRECTION INPUT ;
    USE SIGNAL ;
    PORT
      LAYER MET3 ;
        RECT 82.050 57.850 82.600 57.950 ;
    END
  END W6END_6
  PIN W6END_7
    DIRECTION INPUT ;
    USE SIGNAL ;
    PORT
      LAYER MET3 ;
        RECT 82.050 58.450 82.600 58.550 ;
    END
  END W6END_7
  PIN W6END_8
    DIRECTION INPUT ;
    USE SIGNAL ;
    PORT
      LAYER MET3 ;
        RECT 82.050 59.050 82.600 59.150 ;
    END
  END W6END_8
  PIN W6END_9
    DIRECTION INPUT ;
    USE SIGNAL ;
    PORT
      LAYER MET3 ;
        RECT 82.050 59.650 82.600 59.750 ;
    END
  END W6END_9
  PIN W6END_10
    DIRECTION INPUT ;
    USE SIGNAL ;
    PORT
      LAYER MET3 ;
        RECT 82.050 60.250 82.600 60.350 ;
    END
  END W6END_10
  PIN W6END_11
    DIRECTION INPUT ;
    USE SIGNAL ;
    PORT
      LAYER MET3 ;
        RECT 82.050 60.850 82.600 60.950 ;
    END
  END W6END_11
  PIN E1END_0
    DIRECTION INPUT ;
    USE SIGNAL ;
    PORT
      LAYER MET3 ;
        RECT 0.000 3.850 0.550 3.950 ;
    END
  END E1END_0
  PIN E1END_1
    DIRECTION INPUT ;
    USE SIGNAL ;
    PORT
      LAYER MET3 ;
        RECT 0.000 4.450 0.550 4.550 ;
    END
  END E1END_1
  PIN E1END_2
    DIRECTION INPUT ;
    USE SIGNAL ;
    PORT
      LAYER MET3 ;
        RECT 0.000 5.050 0.550 5.150 ;
    END
  END E1END_2
  PIN E1END_3
    DIRECTION INPUT ;
    USE SIGNAL ;
    PORT
      LAYER MET3 ;
        RECT 0.000 5.650 0.550 5.750 ;
    END
  END E1END_3
  PIN E2MID_0
    DIRECTION INPUT ;
    USE SIGNAL ;
    PORT
      LAYER MET3 ;
        RECT 0.000 6.250 0.550 6.350 ;
    END
  END E2MID_0
  PIN E2MID_1
    DIRECTION INPUT ;
    USE SIGNAL ;
    PORT
      LAYER MET3 ;
        RECT 0.000 6.850 0.550 6.950 ;
    END
  END E2MID_1
  PIN E2MID_2
    DIRECTION INPUT ;
    USE SIGNAL ;
    PORT
      LAYER MET3 ;
        RECT 0.000 7.450 0.550 7.550 ;
    END
  END E2MID_2
  PIN E2MID_3
    DIRECTION INPUT ;
    USE SIGNAL ;
    PORT
      LAYER MET3 ;
        RECT 0.000 8.050 0.550 8.150 ;
    END
  END E2MID_3
  PIN E2MID_4
    DIRECTION INPUT ;
    USE SIGNAL ;
    PORT
      LAYER MET3 ;
        RECT 0.000 8.650 0.550 8.750 ;
    END
  END E2MID_4
  PIN E2MID_5
    DIRECTION INPUT ;
    USE SIGNAL ;
    PORT
      LAYER MET3 ;
        RECT 0.000 9.250 0.550 9.350 ;
    END
  END E2MID_5
  PIN E2MID_6
    DIRECTION INPUT ;
    USE SIGNAL ;
    PORT
      LAYER MET3 ;
        RECT 0.000 9.850 0.550 9.950 ;
    END
  END E2MID_6
  PIN E2MID_7
    DIRECTION INPUT ;
    USE SIGNAL ;
    PORT
      LAYER MET3 ;
        RECT 0.000 10.450 0.550 10.550 ;
    END
  END E2MID_7
  PIN E2END_0
    DIRECTION INPUT ;
    USE SIGNAL ;
    PORT
      LAYER MET3 ;
        RECT 0.000 11.050 0.550 11.150 ;
    END
  END E2END_0
  PIN E2END_1
    DIRECTION INPUT ;
    USE SIGNAL ;
    PORT
      LAYER MET3 ;
        RECT 0.000 11.650 0.550 11.750 ;
    END
  END E2END_1
  PIN E2END_2
    DIRECTION INPUT ;
    USE SIGNAL ;
    PORT
      LAYER MET3 ;
        RECT 0.000 12.250 0.550 12.350 ;
    END
  END E2END_2
  PIN E2END_3
    DIRECTION INPUT ;
    USE SIGNAL ;
    PORT
      LAYER MET3 ;
        RECT 0.000 12.850 0.550 12.950 ;
    END
  END E2END_3
  PIN E2END_4
    DIRECTION INPUT ;
    USE SIGNAL ;
    PORT
      LAYER MET3 ;
        RECT 0.000 13.450 0.550 13.550 ;
    END
  END E2END_4
  PIN E2END_5
    DIRECTION INPUT ;
    USE SIGNAL ;
    PORT
      LAYER MET3 ;
        RECT 0.000 14.050 0.550 14.150 ;
    END
  END E2END_5
  PIN E2END_6
    DIRECTION INPUT ;
    USE SIGNAL ;
    PORT
      LAYER MET3 ;
        RECT 0.000 14.650 0.550 14.750 ;
    END
  END E2END_6
  PIN E2END_7
    DIRECTION INPUT ;
    USE SIGNAL ;
    PORT
      LAYER MET3 ;
        RECT 0.000 15.250 0.550 15.350 ;
    END
  END E2END_7
  PIN EE4END_0
    DIRECTION INPUT ;
    USE SIGNAL ;
    PORT
      LAYER MET3 ;
        RECT 0.000 15.850 0.550 15.950 ;
    END
  END EE4END_0
  PIN EE4END_1
    DIRECTION INPUT ;
    USE SIGNAL ;
    PORT
      LAYER MET3 ;
        RECT 0.000 16.450 0.550 16.550 ;
    END
  END EE4END_1
  PIN EE4END_2
    DIRECTION INPUT ;
    USE SIGNAL ;
    PORT
      LAYER MET3 ;
        RECT 0.000 17.050 0.550 17.150 ;
    END
  END EE4END_2
  PIN EE4END_3
    DIRECTION INPUT ;
    USE SIGNAL ;
    PORT
      LAYER MET3 ;
        RECT 0.000 17.650 0.550 17.750 ;
    END
  END EE4END_3
  PIN EE4END_4
    DIRECTION INPUT ;
    USE SIGNAL ;
    PORT
      LAYER MET3 ;
        RECT 0.000 18.250 0.550 18.350 ;
    END
  END EE4END_4
  PIN EE4END_5
    DIRECTION INPUT ;
    USE SIGNAL ;
    PORT
      LAYER MET3 ;
        RECT 0.000 18.850 0.550 18.950 ;
    END
  END EE4END_5
  PIN EE4END_6
    DIRECTION INPUT ;
    USE SIGNAL ;
    PORT
      LAYER MET3 ;
        RECT 0.000 19.450 0.550 19.550 ;
    END
  END EE4END_6
  PIN EE4END_7
    DIRECTION INPUT ;
    USE SIGNAL ;
    PORT
      LAYER MET3 ;
        RECT 0.000 20.050 0.550 20.150 ;
    END
  END EE4END_7
  PIN EE4END_8
    DIRECTION INPUT ;
    USE SIGNAL ;
    PORT
      LAYER MET3 ;
        RECT 0.000 20.650 0.550 20.750 ;
    END
  END EE4END_8
  PIN EE4END_9
    DIRECTION INPUT ;
    USE SIGNAL ;
    PORT
      LAYER MET3 ;
        RECT 0.000 21.250 0.550 21.350 ;
    END
  END EE4END_9
  PIN EE4END_10
    DIRECTION INPUT ;
    USE SIGNAL ;
    PORT
      LAYER MET3 ;
        RECT 0.000 21.850 0.550 21.950 ;
    END
  END EE4END_10
  PIN EE4END_11
    DIRECTION INPUT ;
    USE SIGNAL ;
    PORT
      LAYER MET3 ;
        RECT 0.000 22.450 0.550 22.550 ;
    END
  END EE4END_11
  PIN EE4END_12
    DIRECTION INPUT ;
    USE SIGNAL ;
    PORT
      LAYER MET3 ;
        RECT 0.000 23.050 0.550 23.150 ;
    END
  END EE4END_12
  PIN EE4END_13
    DIRECTION INPUT ;
    USE SIGNAL ;
    PORT
      LAYER MET3 ;
        RECT 0.000 23.650 0.550 23.750 ;
    END
  END EE4END_13
  PIN EE4END_14
    DIRECTION INPUT ;
    USE SIGNAL ;
    PORT
      LAYER MET3 ;
        RECT 0.000 24.250 0.550 24.350 ;
    END
  END EE4END_14
  PIN EE4END_15
    DIRECTION INPUT ;
    USE SIGNAL ;
    PORT
      LAYER MET3 ;
        RECT 0.000 24.850 0.550 24.950 ;
    END
  END EE4END_15
  PIN E6END_0
    DIRECTION INPUT ;
    USE SIGNAL ;
    PORT
      LAYER MET3 ;
        RECT 0.000 25.450 0.550 25.550 ;
    END
  END E6END_0
  PIN E6END_1
    DIRECTION INPUT ;
    USE SIGNAL ;
    PORT
      LAYER MET3 ;
        RECT 0.000 26.050 0.550 26.150 ;
    END
  END E6END_1
  PIN E6END_2
    DIRECTION INPUT ;
    USE SIGNAL ;
    PORT
      LAYER MET3 ;
        RECT 0.000 26.650 0.550 26.750 ;
    END
  END E6END_2
  PIN E6END_3
    DIRECTION INPUT ;
    USE SIGNAL ;
    PORT
      LAYER MET3 ;
        RECT 0.000 27.250 0.550 27.350 ;
    END
  END E6END_3
  PIN E6END_4
    DIRECTION INPUT ;
    USE SIGNAL ;
    PORT
      LAYER MET3 ;
        RECT 0.000 27.850 0.550 27.950 ;
    END
  END E6END_4
  PIN E6END_5
    DIRECTION INPUT ;
    USE SIGNAL ;
    PORT
      LAYER MET3 ;
        RECT 0.000 28.450 0.550 28.550 ;
    END
  END E6END_5
  PIN E6END_6
    DIRECTION INPUT ;
    USE SIGNAL ;
    PORT
      LAYER MET3 ;
        RECT 0.000 29.050 0.550 29.150 ;
    END
  END E6END_6
  PIN E6END_7
    DIRECTION INPUT ;
    USE SIGNAL ;
    PORT
      LAYER MET3 ;
        RECT 0.000 29.650 0.550 29.750 ;
    END
  END E6END_7
  PIN E6END_8
    DIRECTION INPUT ;
    USE SIGNAL ;
    PORT
      LAYER MET3 ;
        RECT 0.000 30.250 0.550 30.350 ;
    END
  END E6END_8
  PIN E6END_9
    DIRECTION INPUT ;
    USE SIGNAL ;
    PORT
      LAYER MET3 ;
        RECT 0.000 30.850 0.550 30.950 ;
    END
  END E6END_9
  PIN E6END_10
    DIRECTION INPUT ;
    USE SIGNAL ;
    PORT
      LAYER MET3 ;
        RECT 0.000 31.450 0.550 31.550 ;
    END
  END E6END_10
  PIN E6END_11
    DIRECTION INPUT ;
    USE SIGNAL ;
    PORT
      LAYER MET3 ;
        RECT 0.000 32.050 0.550 32.150 ;
    END
  END E6END_11
  PIN W1BEG_0
    DIRECTION OUTPUT ;
    USE SIGNAL ;
    PORT
      LAYER MET3 ;
        RECT 0.000 32.650 0.550 32.750 ;
    END
  END W1BEG_0
  PIN W1BEG_1
    DIRECTION OUTPUT ;
    USE SIGNAL ;
    PORT
      LAYER MET3 ;
        RECT 0.000 33.250 0.550 33.350 ;
    END
  END W1BEG_1
  PIN W1BEG_2
    DIRECTION OUTPUT ;
    USE SIGNAL ;
    PORT
      LAYER MET3 ;
        RECT 0.000 33.850 0.550 33.950 ;
    END
  END W1BEG_2
  PIN W1BEG_3
    DIRECTION OUTPUT ;
    USE SIGNAL ;
    PORT
      LAYER MET3 ;
        RECT 0.000 34.450 0.550 34.550 ;
    END
  END W1BEG_3
  PIN W2BEG_0
    DIRECTION OUTPUT ;
    USE SIGNAL ;
    PORT
      LAYER MET3 ;
        RECT 0.000 35.050 0.550 35.150 ;
    END
  END W2BEG_0
  PIN W2BEG_1
    DIRECTION OUTPUT ;
    USE SIGNAL ;
    PORT
      LAYER MET3 ;
        RECT 0.000 35.650 0.550 35.750 ;
    END
  END W2BEG_1
  PIN W2BEG_2
    DIRECTION OUTPUT ;
    USE SIGNAL ;
    PORT
      LAYER MET3 ;
        RECT 0.000 36.250 0.550 36.350 ;
    END
  END W2BEG_2
  PIN W2BEG_3
    DIRECTION OUTPUT ;
    USE SIGNAL ;
    PORT
      LAYER MET3 ;
        RECT 0.000 36.850 0.550 36.950 ;
    END
  END W2BEG_3
  PIN W2BEG_4
    DIRECTION OUTPUT ;
    USE SIGNAL ;
    PORT
      LAYER MET3 ;
        RECT 0.000 37.450 0.550 37.550 ;
    END
  END W2BEG_4
  PIN W2BEG_5
    DIRECTION OUTPUT ;
    USE SIGNAL ;
    PORT
      LAYER MET3 ;
        RECT 0.000 38.050 0.550 38.150 ;
    END
  END W2BEG_5
  PIN W2BEG_6
    DIRECTION OUTPUT ;
    USE SIGNAL ;
    PORT
      LAYER MET3 ;
        RECT 0.000 38.650 0.550 38.750 ;
    END
  END W2BEG_6
  PIN W2BEG_7
    DIRECTION OUTPUT ;
    USE SIGNAL ;
    PORT
      LAYER MET3 ;
        RECT 0.000 39.250 0.550 39.350 ;
    END
  END W2BEG_7
  PIN W2BEGb_0
    DIRECTION OUTPUT ;
    USE SIGNAL ;
    PORT
      LAYER MET3 ;
        RECT 0.000 39.850 0.550 39.950 ;
    END
  END W2BEGb_0
  PIN W2BEGb_1
    DIRECTION OUTPUT ;
    USE SIGNAL ;
    PORT
      LAYER MET3 ;
        RECT 0.000 40.450 0.550 40.550 ;
    END
  END W2BEGb_1
  PIN W2BEGb_2
    DIRECTION OUTPUT ;
    USE SIGNAL ;
    PORT
      LAYER MET3 ;
        RECT 0.000 41.050 0.550 41.150 ;
    END
  END W2BEGb_2
  PIN W2BEGb_3
    DIRECTION OUTPUT ;
    USE SIGNAL ;
    PORT
      LAYER MET3 ;
        RECT 0.000 41.650 0.550 41.750 ;
    END
  END W2BEGb_3
  PIN W2BEGb_4
    DIRECTION OUTPUT ;
    USE SIGNAL ;
    PORT
      LAYER MET3 ;
        RECT 0.000 42.250 0.550 42.350 ;
    END
  END W2BEGb_4
  PIN W2BEGb_5
    DIRECTION OUTPUT ;
    USE SIGNAL ;
    PORT
      LAYER MET3 ;
        RECT 0.000 42.850 0.550 42.950 ;
    END
  END W2BEGb_5
  PIN W2BEGb_6
    DIRECTION OUTPUT ;
    USE SIGNAL ;
    PORT
      LAYER MET3 ;
        RECT 0.000 43.450 0.550 43.550 ;
    END
  END W2BEGb_6
  PIN W2BEGb_7
    DIRECTION OUTPUT ;
    USE SIGNAL ;
    PORT
      LAYER MET3 ;
        RECT 0.000 44.050 0.550 44.150 ;
    END
  END W2BEGb_7
  PIN WW4BEG_0
    DIRECTION OUTPUT ;
    USE SIGNAL ;
    PORT
      LAYER MET3 ;
        RECT 0.000 44.650 0.550 44.750 ;
    END
  END WW4BEG_0
  PIN WW4BEG_1
    DIRECTION OUTPUT ;
    USE SIGNAL ;
    PORT
      LAYER MET3 ;
        RECT 0.000 45.250 0.550 45.350 ;
    END
  END WW4BEG_1
  PIN WW4BEG_2
    DIRECTION OUTPUT ;
    USE SIGNAL ;
    PORT
      LAYER MET3 ;
        RECT 0.000 45.850 0.550 45.950 ;
    END
  END WW4BEG_2
  PIN WW4BEG_3
    DIRECTION OUTPUT ;
    USE SIGNAL ;
    PORT
      LAYER MET3 ;
        RECT 0.000 46.450 0.550 46.550 ;
    END
  END WW4BEG_3
  PIN WW4BEG_4
    DIRECTION OUTPUT ;
    USE SIGNAL ;
    PORT
      LAYER MET3 ;
        RECT 0.000 47.050 0.550 47.150 ;
    END
  END WW4BEG_4
  PIN WW4BEG_5
    DIRECTION OUTPUT ;
    USE SIGNAL ;
    PORT
      LAYER MET3 ;
        RECT 0.000 47.650 0.550 47.750 ;
    END
  END WW4BEG_5
  PIN WW4BEG_6
    DIRECTION OUTPUT ;
    USE SIGNAL ;
    PORT
      LAYER MET3 ;
        RECT 0.000 48.250 0.550 48.350 ;
    END
  END WW4BEG_6
  PIN WW4BEG_7
    DIRECTION OUTPUT ;
    USE SIGNAL ;
    PORT
      LAYER MET3 ;
        RECT 0.000 48.850 0.550 48.950 ;
    END
  END WW4BEG_7
  PIN WW4BEG_8
    DIRECTION OUTPUT ;
    USE SIGNAL ;
    PORT
      LAYER MET3 ;
        RECT 0.000 49.450 0.550 49.550 ;
    END
  END WW4BEG_8
  PIN WW4BEG_9
    DIRECTION OUTPUT ;
    USE SIGNAL ;
    PORT
      LAYER MET3 ;
        RECT 0.000 50.050 0.550 50.150 ;
    END
  END WW4BEG_9
  PIN WW4BEG_10
    DIRECTION OUTPUT ;
    USE SIGNAL ;
    PORT
      LAYER MET3 ;
        RECT 0.000 50.650 0.550 50.750 ;
    END
  END WW4BEG_10
  PIN WW4BEG_11
    DIRECTION OUTPUT ;
    USE SIGNAL ;
    PORT
      LAYER MET3 ;
        RECT 0.000 51.250 0.550 51.350 ;
    END
  END WW4BEG_11
  PIN WW4BEG_12
    DIRECTION OUTPUT ;
    USE SIGNAL ;
    PORT
      LAYER MET3 ;
        RECT 0.000 51.850 0.550 51.950 ;
    END
  END WW4BEG_12
  PIN WW4BEG_13
    DIRECTION OUTPUT ;
    USE SIGNAL ;
    PORT
      LAYER MET3 ;
        RECT 0.000 52.450 0.550 52.550 ;
    END
  END WW4BEG_13
  PIN WW4BEG_14
    DIRECTION OUTPUT ;
    USE SIGNAL ;
    PORT
      LAYER MET3 ;
        RECT 0.000 53.050 0.550 53.150 ;
    END
  END WW4BEG_14
  PIN WW4BEG_15
    DIRECTION OUTPUT ;
    USE SIGNAL ;
    PORT
      LAYER MET3 ;
        RECT 0.000 53.650 0.550 53.750 ;
    END
  END WW4BEG_15
  PIN W6BEG_0
    DIRECTION OUTPUT ;
    USE SIGNAL ;
    PORT
      LAYER MET3 ;
        RECT 0.000 54.250 0.550 54.350 ;
    END
  END W6BEG_0
  PIN W6BEG_1
    DIRECTION OUTPUT ;
    USE SIGNAL ;
    PORT
      LAYER MET3 ;
        RECT 0.000 54.850 0.550 54.950 ;
    END
  END W6BEG_1
  PIN W6BEG_2
    DIRECTION OUTPUT ;
    USE SIGNAL ;
    PORT
      LAYER MET3 ;
        RECT 0.000 55.450 0.550 55.550 ;
    END
  END W6BEG_2
  PIN W6BEG_3
    DIRECTION OUTPUT ;
    USE SIGNAL ;
    PORT
      LAYER MET3 ;
        RECT 0.000 56.050 0.550 56.150 ;
    END
  END W6BEG_3
  PIN W6BEG_4
    DIRECTION OUTPUT ;
    USE SIGNAL ;
    PORT
      LAYER MET3 ;
        RECT 0.000 56.650 0.550 56.750 ;
    END
  END W6BEG_4
  PIN W6BEG_5
    DIRECTION OUTPUT ;
    USE SIGNAL ;
    PORT
      LAYER MET3 ;
        RECT 0.000 57.250 0.550 57.350 ;
    END
  END W6BEG_5
  PIN W6BEG_6
    DIRECTION OUTPUT ;
    USE SIGNAL ;
    PORT
      LAYER MET3 ;
        RECT 0.000 57.850 0.550 57.950 ;
    END
  END W6BEG_6
  PIN W6BEG_7
    DIRECTION OUTPUT ;
    USE SIGNAL ;
    PORT
      LAYER MET3 ;
        RECT 0.000 58.450 0.550 58.550 ;
    END
  END W6BEG_7
  PIN W6BEG_8
    DIRECTION OUTPUT ;
    USE SIGNAL ;
    PORT
      LAYER MET3 ;
        RECT 0.000 59.050 0.550 59.150 ;
    END
  END W6BEG_8
  PIN W6BEG_9
    DIRECTION OUTPUT ;
    USE SIGNAL ;
    PORT
      LAYER MET3 ;
        RECT 0.000 59.650 0.550 59.750 ;
    END
  END W6BEG_9
  PIN W6BEG_10
    DIRECTION OUTPUT ;
    USE SIGNAL ;
    PORT
      LAYER MET3 ;
        RECT 0.000 60.250 0.550 60.350 ;
    END
  END W6BEG_10
  PIN W6BEG_11
    DIRECTION OUTPUT ;
    USE SIGNAL ;
    PORT
      LAYER MET3 ;
        RECT 0.000 60.850 0.550 60.950 ;
    END
  END W6BEG_11
  PIN N_GBUF_END_0
    DIRECTION INPUT ;
    USE SIGNAL ;
    PORT
      LAYER MET4 ;
        RECT 9.250 0.000 9.350 0.550 ;
    END
  END N_GBUF_END_0
  PIN N_GBUF_END_1
    DIRECTION INPUT ;
    USE SIGNAL ;
    PORT
      LAYER MET4 ;
        RECT 9.650 0.000 9.750 0.550 ;
    END
  END N_GBUF_END_1
  PIN N_GBUF_END_2
    DIRECTION INPUT ;
    USE SIGNAL ;
    PORT
      LAYER MET4 ;
        RECT 10.050 0.000 10.150 0.550 ;
    END
  END N_GBUF_END_2
  PIN N_GBUF_END_3
    DIRECTION INPUT ;
    USE SIGNAL ;
    PORT
      LAYER MET4 ;
        RECT 10.450 0.000 10.550 0.550 ;
    END
  END N_GBUF_END_3
  PIN N1END_0
    DIRECTION INPUT ;
    USE SIGNAL ;
    PORT
      LAYER MET4 ;
        RECT 12.450 0.000 12.550 0.550 ;
    END
  END N1END_0
  PIN N1END_1
    DIRECTION INPUT ;
    USE SIGNAL ;
    PORT
      LAYER MET4 ;
        RECT 12.850 0.000 12.950 0.550 ;
    END
  END N1END_1
  PIN N1END_2
    DIRECTION INPUT ;
    USE SIGNAL ;
    PORT
      LAYER MET4 ;
        RECT 13.250 0.000 13.350 0.550 ;
    END
  END N1END_2
  PIN N1END_3
    DIRECTION INPUT ;
    USE SIGNAL ;
    PORT
      LAYER MET4 ;
        RECT 13.650 0.000 13.750 0.550 ;
    END
  END N1END_3
  PIN N2MID_0
    DIRECTION INPUT ;
    USE SIGNAL ;
    PORT
      LAYER MET4 ;
        RECT 14.050 0.000 14.150 0.550 ;
    END
  END N2MID_0
  PIN N2MID_1
    DIRECTION INPUT ;
    USE SIGNAL ;
    PORT
      LAYER MET4 ;
        RECT 14.450 0.000 14.550 0.550 ;
    END
  END N2MID_1
  PIN N2MID_2
    DIRECTION INPUT ;
    USE SIGNAL ;
    PORT
      LAYER MET4 ;
        RECT 14.850 0.000 14.950 0.550 ;
    END
  END N2MID_2
  PIN N2MID_3
    DIRECTION INPUT ;
    USE SIGNAL ;
    PORT
      LAYER MET4 ;
        RECT 15.250 0.000 15.350 0.550 ;
    END
  END N2MID_3
  PIN N2MID_4
    DIRECTION INPUT ;
    USE SIGNAL ;
    PORT
      LAYER MET4 ;
        RECT 15.650 0.000 15.750 0.550 ;
    END
  END N2MID_4
  PIN N2MID_5
    DIRECTION INPUT ;
    USE SIGNAL ;
    PORT
      LAYER MET4 ;
        RECT 16.050 0.000 16.150 0.550 ;
    END
  END N2MID_5
  PIN N2MID_6
    DIRECTION INPUT ;
    USE SIGNAL ;
    PORT
      LAYER MET4 ;
        RECT 16.450 0.000 16.550 0.550 ;
    END
  END N2MID_6
  PIN N2MID_7
    DIRECTION INPUT ;
    USE SIGNAL ;
    PORT
      LAYER MET4 ;
        RECT 16.850 0.000 16.950 0.550 ;
    END
  END N2MID_7
  PIN N2END_0
    DIRECTION INPUT ;
    USE SIGNAL ;
    PORT
      LAYER MET4 ;
        RECT 17.250 0.000 17.350 0.550 ;
    END
  END N2END_0
  PIN N2END_1
    DIRECTION INPUT ;
    USE SIGNAL ;
    PORT
      LAYER MET4 ;
        RECT 17.650 0.000 17.750 0.550 ;
    END
  END N2END_1
  PIN N2END_2
    DIRECTION INPUT ;
    USE SIGNAL ;
    PORT
      LAYER MET4 ;
        RECT 18.050 0.000 18.150 0.550 ;
    END
  END N2END_2
  PIN N2END_3
    DIRECTION INPUT ;
    USE SIGNAL ;
    PORT
      LAYER MET4 ;
        RECT 18.450 0.000 18.550 0.550 ;
    END
  END N2END_3
  PIN N2END_4
    DIRECTION INPUT ;
    USE SIGNAL ;
    PORT
      LAYER MET4 ;
        RECT 18.850 0.000 18.950 0.550 ;
    END
  END N2END_4
  PIN N2END_5
    DIRECTION INPUT ;
    USE SIGNAL ;
    PORT
      LAYER MET4 ;
        RECT 20.850 0.000 20.950 0.550 ;
    END
  END N2END_5
  PIN N2END_6
    DIRECTION INPUT ;
    USE SIGNAL ;
    PORT
      LAYER MET4 ;
        RECT 21.250 0.000 21.350 0.550 ;
    END
  END N2END_6
  PIN N2END_7
    DIRECTION INPUT ;
    USE SIGNAL ;
    PORT
      LAYER MET4 ;
        RECT 21.650 0.000 21.750 0.550 ;
    END
  END N2END_7
  PIN N4END_0
    DIRECTION INPUT ;
    USE SIGNAL ;
    PORT
      LAYER MET4 ;
        RECT 22.050 0.000 22.150 0.550 ;
    END
  END N4END_0
  PIN N4END_1
    DIRECTION INPUT ;
    USE SIGNAL ;
    PORT
      LAYER MET4 ;
        RECT 22.450 0.000 22.550 0.550 ;
    END
  END N4END_1
  PIN N4END_2
    DIRECTION INPUT ;
    USE SIGNAL ;
    PORT
      LAYER MET4 ;
        RECT 22.850 0.000 22.950 0.550 ;
    END
  END N4END_2
  PIN N4END_3
    DIRECTION INPUT ;
    USE SIGNAL ;
    PORT
      LAYER MET4 ;
        RECT 23.250 0.000 23.350 0.550 ;
    END
  END N4END_3
  PIN N4END_4
    DIRECTION INPUT ;
    USE SIGNAL ;
    PORT
      LAYER MET4 ;
        RECT 23.650 0.000 23.750 0.550 ;
    END
  END N4END_4
  PIN N4END_5
    DIRECTION INPUT ;
    USE SIGNAL ;
    PORT
      LAYER MET4 ;
        RECT 24.050 0.000 24.150 0.550 ;
    END
  END N4END_5
  PIN N4END_6
    DIRECTION INPUT ;
    USE SIGNAL ;
    PORT
      LAYER MET4 ;
        RECT 24.450 0.000 24.550 0.550 ;
    END
  END N4END_6
  PIN N4END_7
    DIRECTION INPUT ;
    USE SIGNAL ;
    PORT
      LAYER MET4 ;
        RECT 24.850 0.000 24.950 0.550 ;
    END
  END N4END_7
  PIN N4END_8
    DIRECTION INPUT ;
    USE SIGNAL ;
    PORT
      LAYER MET4 ;
        RECT 25.250 0.000 25.350 0.550 ;
    END
  END N4END_8
  PIN N4END_9
    DIRECTION INPUT ;
    USE SIGNAL ;
    PORT
      LAYER MET4 ;
        RECT 25.650 0.000 25.750 0.550 ;
    END
  END N4END_9
  PIN N4END_10
    DIRECTION INPUT ;
    USE SIGNAL ;
    PORT
      LAYER MET4 ;
        RECT 26.050 0.000 26.150 0.550 ;
    END
  END N4END_10
  PIN N4END_11
    DIRECTION INPUT ;
    USE SIGNAL ;
    PORT
      LAYER MET4 ;
        RECT 26.450 0.000 26.550 0.550 ;
    END
  END N4END_11
  PIN N4END_12
    DIRECTION INPUT ;
    USE SIGNAL ;
    PORT
      LAYER MET4 ;
        RECT 26.850 0.000 26.950 0.550 ;
    END
  END N4END_12
  PIN N4END_13
    DIRECTION INPUT ;
    USE SIGNAL ;
    PORT
      LAYER MET4 ;
        RECT 27.250 0.000 27.350 0.550 ;
    END
  END N4END_13
  PIN N4END_14
    DIRECTION INPUT ;
    USE SIGNAL ;
    PORT
      LAYER MET4 ;
        RECT 29.250 0.000 29.350 0.550 ;
    END
  END N4END_14
  PIN N4END_15
    DIRECTION INPUT ;
    USE SIGNAL ;
    PORT
      LAYER MET4 ;
        RECT 29.650 0.000 29.750 0.550 ;
    END
  END N4END_15
  PIN NN4END_0
    DIRECTION INPUT ;
    USE SIGNAL ;
    PORT
      LAYER MET4 ;
        RECT 30.050 0.000 30.150 0.550 ;
    END
  END NN4END_0
  PIN NN4END_1
    DIRECTION INPUT ;
    USE SIGNAL ;
    PORT
      LAYER MET4 ;
        RECT 30.450 0.000 30.550 0.550 ;
    END
  END NN4END_1
  PIN NN4END_2
    DIRECTION INPUT ;
    USE SIGNAL ;
    PORT
      LAYER MET4 ;
        RECT 30.850 0.000 30.950 0.550 ;
    END
  END NN4END_2
  PIN NN4END_3
    DIRECTION INPUT ;
    USE SIGNAL ;
    PORT
      LAYER MET4 ;
        RECT 31.250 0.000 31.350 0.550 ;
    END
  END NN4END_3
  PIN NN4END_4
    DIRECTION INPUT ;
    USE SIGNAL ;
    PORT
      LAYER MET4 ;
        RECT 31.650 0.000 31.750 0.550 ;
    END
  END NN4END_4
  PIN NN4END_5
    DIRECTION INPUT ;
    USE SIGNAL ;
    PORT
      LAYER MET4 ;
        RECT 32.050 0.000 32.150 0.550 ;
    END
  END NN4END_5
  PIN NN4END_6
    DIRECTION INPUT ;
    USE SIGNAL ;
    PORT
      LAYER MET4 ;
        RECT 32.450 0.000 32.550 0.550 ;
    END
  END NN4END_6
  PIN NN4END_7
    DIRECTION INPUT ;
    USE SIGNAL ;
    PORT
      LAYER MET4 ;
        RECT 32.850 0.000 32.950 0.550 ;
    END
  END NN4END_7
  PIN NN4END_8
    DIRECTION INPUT ;
    USE SIGNAL ;
    PORT
      LAYER MET4 ;
        RECT 33.250 0.000 33.350 0.550 ;
    END
  END NN4END_8
  PIN NN4END_9
    DIRECTION INPUT ;
    USE SIGNAL ;
    PORT
      LAYER MET4 ;
        RECT 33.650 0.000 33.750 0.550 ;
    END
  END NN4END_9
  PIN NN4END_10
    DIRECTION INPUT ;
    USE SIGNAL ;
    PORT
      LAYER MET4 ;
        RECT 34.050 0.000 34.150 0.550 ;
    END
  END NN4END_10
  PIN NN4END_11
    DIRECTION INPUT ;
    USE SIGNAL ;
    PORT
      LAYER MET4 ;
        RECT 34.450 0.000 34.550 0.550 ;
    END
  END NN4END_11
  PIN NN4END_12
    DIRECTION INPUT ;
    USE SIGNAL ;
    PORT
      LAYER MET4 ;
        RECT 34.850 0.000 34.950 0.550 ;
    END
  END NN4END_12
  PIN NN4END_13
    DIRECTION INPUT ;
    USE SIGNAL ;
    PORT
      LAYER MET4 ;
        RECT 35.250 0.000 35.350 0.550 ;
    END
  END NN4END_13
  PIN NN4END_14
    DIRECTION INPUT ;
    USE SIGNAL ;
    PORT
      LAYER MET4 ;
        RECT 35.650 0.000 35.750 0.550 ;
    END
  END NN4END_14
  PIN NN4END_15
    DIRECTION INPUT ;
    USE SIGNAL ;
    PORT
      LAYER MET4 ;
        RECT 37.650 0.000 37.750 0.550 ;
    END
  END NN4END_15
  PIN S1BEG_0
    DIRECTION OUTPUT ;
    USE SIGNAL ;
    PORT
      LAYER MET4 ;
        RECT 38.450 0.000 38.550 0.550 ;
    END
  END S1BEG_0
  PIN S1BEG_1
    DIRECTION OUTPUT ;
    USE SIGNAL ;
    PORT
      LAYER MET4 ;
        RECT 38.850 0.000 38.950 0.550 ;
    END
  END S1BEG_1
  PIN S1BEG_2
    DIRECTION OUTPUT ;
    USE SIGNAL ;
    PORT
      LAYER MET4 ;
        RECT 39.250 0.000 39.350 0.550 ;
    END
  END S1BEG_2
  PIN S1BEG_3
    DIRECTION OUTPUT ;
    USE SIGNAL ;
    PORT
      LAYER MET4 ;
        RECT 39.650 0.000 39.750 0.550 ;
    END
  END S1BEG_3
  PIN S2BEG_0
    DIRECTION OUTPUT ;
    USE SIGNAL ;
    PORT
      LAYER MET4 ;
        RECT 40.050 0.000 40.150 0.550 ;
    END
  END S2BEG_0
  PIN S2BEG_1
    DIRECTION OUTPUT ;
    USE SIGNAL ;
    PORT
      LAYER MET4 ;
        RECT 40.450 0.000 40.550 0.550 ;
    END
  END S2BEG_1
  PIN S2BEG_2
    DIRECTION OUTPUT ;
    USE SIGNAL ;
    PORT
      LAYER MET4 ;
        RECT 40.850 0.000 40.950 0.550 ;
    END
  END S2BEG_2
  PIN S2BEG_3
    DIRECTION OUTPUT ;
    USE SIGNAL ;
    PORT
      LAYER MET4 ;
        RECT 41.250 0.000 41.350 0.550 ;
    END
  END S2BEG_3
  PIN S2BEG_4
    DIRECTION OUTPUT ;
    USE SIGNAL ;
    PORT
      LAYER MET4 ;
        RECT 41.650 0.000 41.750 0.550 ;
    END
  END S2BEG_4
  PIN S2BEG_5
    DIRECTION OUTPUT ;
    USE SIGNAL ;
    PORT
      LAYER MET4 ;
        RECT 42.050 0.000 42.150 0.550 ;
    END
  END S2BEG_5
  PIN S2BEG_6
    DIRECTION OUTPUT ;
    USE SIGNAL ;
    PORT
      LAYER MET4 ;
        RECT 42.450 0.000 42.550 0.550 ;
    END
  END S2BEG_6
  PIN S2BEG_7
    DIRECTION OUTPUT ;
    USE SIGNAL ;
    PORT
      LAYER MET4 ;
        RECT 42.850 0.000 42.950 0.550 ;
    END
  END S2BEG_7
  PIN S2BEGb_0
    DIRECTION OUTPUT ;
    USE SIGNAL ;
    PORT
      LAYER MET4 ;
        RECT 43.250 0.000 43.350 0.550 ;
    END
  END S2BEGb_0
  PIN S2BEGb_1
    DIRECTION OUTPUT ;
    USE SIGNAL ;
    PORT
      LAYER MET4 ;
        RECT 43.650 0.000 43.750 0.550 ;
    END
  END S2BEGb_1
  PIN S2BEGb_2
    DIRECTION OUTPUT ;
    USE SIGNAL ;
    PORT
      LAYER MET4 ;
        RECT 44.050 0.000 44.150 0.550 ;
    END
  END S2BEGb_2
  PIN S2BEGb_3
    DIRECTION OUTPUT ;
    USE SIGNAL ;
    PORT
      LAYER MET4 ;
        RECT 46.050 0.000 46.150 0.550 ;
    END
  END S2BEGb_3
  PIN S2BEGb_4
    DIRECTION OUTPUT ;
    USE SIGNAL ;
    PORT
      LAYER MET4 ;
        RECT 46.450 0.000 46.550 0.550 ;
    END
  END S2BEGb_4
  PIN S2BEGb_5
    DIRECTION OUTPUT ;
    USE SIGNAL ;
    PORT
      LAYER MET4 ;
        RECT 46.850 0.000 46.950 0.550 ;
    END
  END S2BEGb_5
  PIN S2BEGb_6
    DIRECTION OUTPUT ;
    USE SIGNAL ;
    PORT
      LAYER MET4 ;
        RECT 47.250 0.000 47.350 0.550 ;
    END
  END S2BEGb_6
  PIN S2BEGb_7
    DIRECTION OUTPUT ;
    USE SIGNAL ;
    PORT
      LAYER MET4 ;
        RECT 47.650 0.000 47.750 0.550 ;
    END
  END S2BEGb_7
  PIN S4BEG_0
    DIRECTION OUTPUT ;
    USE SIGNAL ;
    PORT
      LAYER MET4 ;
        RECT 48.050 0.000 48.150 0.550 ;
    END
  END S4BEG_0
  PIN S4BEG_1
    DIRECTION OUTPUT ;
    USE SIGNAL ;
    PORT
      LAYER MET4 ;
        RECT 48.450 0.000 48.550 0.550 ;
    END
  END S4BEG_1
  PIN S4BEG_2
    DIRECTION OUTPUT ;
    USE SIGNAL ;
    PORT
      LAYER MET4 ;
        RECT 48.850 0.000 48.950 0.550 ;
    END
  END S4BEG_2
  PIN S4BEG_3
    DIRECTION OUTPUT ;
    USE SIGNAL ;
    PORT
      LAYER MET4 ;
        RECT 49.250 0.000 49.350 0.550 ;
    END
  END S4BEG_3
  PIN S4BEG_4
    DIRECTION OUTPUT ;
    USE SIGNAL ;
    PORT
      LAYER MET4 ;
        RECT 49.650 0.000 49.750 0.550 ;
    END
  END S4BEG_4
  PIN S4BEG_5
    DIRECTION OUTPUT ;
    USE SIGNAL ;
    PORT
      LAYER MET4 ;
        RECT 50.050 0.000 50.150 0.550 ;
    END
  END S4BEG_5
  PIN S4BEG_6
    DIRECTION OUTPUT ;
    USE SIGNAL ;
    PORT
      LAYER MET4 ;
        RECT 50.450 0.000 50.550 0.550 ;
    END
  END S4BEG_6
  PIN S4BEG_7
    DIRECTION OUTPUT ;
    USE SIGNAL ;
    PORT
      LAYER MET4 ;
        RECT 50.850 0.000 50.950 0.550 ;
    END
  END S4BEG_7
  PIN S4BEG_8
    DIRECTION OUTPUT ;
    USE SIGNAL ;
    PORT
      LAYER MET4 ;
        RECT 51.250 0.000 51.350 0.550 ;
    END
  END S4BEG_8
  PIN S4BEG_9
    DIRECTION OUTPUT ;
    USE SIGNAL ;
    PORT
      LAYER MET4 ;
        RECT 51.650 0.000 51.750 0.550 ;
    END
  END S4BEG_9
  PIN S4BEG_10
    DIRECTION OUTPUT ;
    USE SIGNAL ;
    PORT
      LAYER MET4 ;
        RECT 52.050 0.000 52.150 0.550 ;
    END
  END S4BEG_10
  PIN S4BEG_11
    DIRECTION OUTPUT ;
    USE SIGNAL ;
    PORT
      LAYER MET4 ;
        RECT 52.450 0.000 52.550 0.550 ;
    END
  END S4BEG_11
  PIN S4BEG_12
    DIRECTION OUTPUT ;
    USE SIGNAL ;
    PORT
      LAYER MET4 ;
        RECT 54.450 0.000 54.550 0.550 ;
    END
  END S4BEG_12
  PIN S4BEG_13
    DIRECTION OUTPUT ;
    USE SIGNAL ;
    PORT
      LAYER MET4 ;
        RECT 54.850 0.000 54.950 0.550 ;
    END
  END S4BEG_13
  PIN S4BEG_14
    DIRECTION OUTPUT ;
    USE SIGNAL ;
    PORT
      LAYER MET4 ;
        RECT 55.250 0.000 55.350 0.550 ;
    END
  END S4BEG_14
  PIN S4BEG_15
    DIRECTION OUTPUT ;
    USE SIGNAL ;
    PORT
      LAYER MET4 ;
        RECT 55.650 0.000 55.750 0.550 ;
    END
  END S4BEG_15
  PIN SS4BEG_0
    DIRECTION OUTPUT ;
    USE SIGNAL ;
    PORT
      LAYER MET4 ;
        RECT 56.050 0.000 56.150 0.550 ;
    END
  END SS4BEG_0
  PIN SS4BEG_1
    DIRECTION OUTPUT ;
    USE SIGNAL ;
    PORT
      LAYER MET4 ;
        RECT 56.450 0.000 56.550 0.550 ;
    END
  END SS4BEG_1
  PIN SS4BEG_2
    DIRECTION OUTPUT ;
    USE SIGNAL ;
    PORT
      LAYER MET4 ;
        RECT 56.850 0.000 56.950 0.550 ;
    END
  END SS4BEG_2
  PIN SS4BEG_3
    DIRECTION OUTPUT ;
    USE SIGNAL ;
    PORT
      LAYER MET4 ;
        RECT 57.250 0.000 57.350 0.550 ;
    END
  END SS4BEG_3
  PIN SS4BEG_4
    DIRECTION OUTPUT ;
    USE SIGNAL ;
    PORT
      LAYER MET4 ;
        RECT 57.650 0.000 57.750 0.550 ;
    END
  END SS4BEG_4
  PIN SS4BEG_5
    DIRECTION OUTPUT ;
    USE SIGNAL ;
    PORT
      LAYER MET4 ;
        RECT 58.050 0.000 58.150 0.550 ;
    END
  END SS4BEG_5
  PIN SS4BEG_6
    DIRECTION OUTPUT ;
    USE SIGNAL ;
    PORT
      LAYER MET4 ;
        RECT 58.450 0.000 58.550 0.550 ;
    END
  END SS4BEG_6
  PIN SS4BEG_7
    DIRECTION OUTPUT ;
    USE SIGNAL ;
    PORT
      LAYER MET4 ;
        RECT 58.850 0.000 58.950 0.550 ;
    END
  END SS4BEG_7
  PIN SS4BEG_8
    DIRECTION OUTPUT ;
    USE SIGNAL ;
    PORT
      LAYER MET4 ;
        RECT 59.250 0.000 59.350 0.550 ;
    END
  END SS4BEG_8
  PIN SS4BEG_9
    DIRECTION OUTPUT ;
    USE SIGNAL ;
    PORT
      LAYER MET4 ;
        RECT 59.650 0.000 59.750 0.550 ;
    END
  END SS4BEG_9
  PIN SS4BEG_10
    DIRECTION OUTPUT ;
    USE SIGNAL ;
    PORT
      LAYER MET4 ;
        RECT 60.050 0.000 60.150 0.550 ;
    END
  END SS4BEG_10
  PIN SS4BEG_11
    DIRECTION OUTPUT ;
    USE SIGNAL ;
    PORT
      LAYER MET4 ;
        RECT 60.450 0.000 60.550 0.550 ;
    END
  END SS4BEG_11
  PIN SS4BEG_12
    DIRECTION OUTPUT ;
    USE SIGNAL ;
    PORT
      LAYER MET4 ;
        RECT 60.850 0.000 60.950 0.550 ;
    END
  END SS4BEG_12
  PIN SS4BEG_13
    DIRECTION OUTPUT ;
    USE SIGNAL ;
    PORT
      LAYER MET4 ;
        RECT 62.850 0.000 62.950 0.550 ;
    END
  END SS4BEG_13
  PIN SS4BEG_14
    DIRECTION OUTPUT ;
    USE SIGNAL ;
    PORT
      LAYER MET4 ;
        RECT 63.250 0.000 63.350 0.550 ;
    END
  END SS4BEG_14
  PIN SS4BEG_15
    DIRECTION OUTPUT ;
    USE SIGNAL ;
    PORT
      LAYER MET4 ;
        RECT 63.650 0.000 63.750 0.550 ;
    END
  END SS4BEG_15
  PIN CI_0
    DIRECTION INPUT ;
    USE SIGNAL ;
    PORT
      LAYER MET4 ;
        RECT 38.050 0.000 38.150 0.550 ;
    END
  END CI_0
  PIN FrameData_0
    DIRECTION INPUT ;
    USE SIGNAL ;
    PORT
      LAYER MET3 ;
        RECT 0.000 61.450 0.550 61.550 ;
    END
  END FrameData_0
  PIN FrameData_1
    DIRECTION INPUT ;
    USE SIGNAL ;
    PORT
      LAYER MET3 ;
        RECT 0.000 62.050 0.550 62.150 ;
    END
  END FrameData_1
  PIN FrameData_2
    DIRECTION INPUT ;
    USE SIGNAL ;
    PORT
      LAYER MET3 ;
        RECT 0.000 62.650 0.550 62.750 ;
    END
  END FrameData_2
  PIN FrameData_3
    DIRECTION INPUT ;
    USE SIGNAL ;
    PORT
      LAYER MET3 ;
        RECT 0.000 63.250 0.550 63.350 ;
    END
  END FrameData_3
  PIN FrameData_4
    DIRECTION INPUT ;
    USE SIGNAL ;
    PORT
      LAYER MET3 ;
        RECT 0.000 63.850 0.550 63.950 ;
    END
  END FrameData_4
  PIN FrameData_5
    DIRECTION INPUT ;
    USE SIGNAL ;
    PORT
      LAYER MET3 ;
        RECT 0.000 64.450 0.550 64.550 ;
    END
  END FrameData_5
  PIN FrameData_6
    DIRECTION INPUT ;
    USE SIGNAL ;
    PORT
      LAYER MET3 ;
        RECT 0.000 65.050 0.550 65.150 ;
    END
  END FrameData_6
  PIN FrameData_7
    DIRECTION INPUT ;
    USE SIGNAL ;
    PORT
      LAYER MET3 ;
        RECT 0.000 65.650 0.550 65.750 ;
    END
  END FrameData_7
  PIN FrameData_8
    DIRECTION INPUT ;
    USE SIGNAL ;
    PORT
      LAYER MET3 ;
        RECT 0.000 66.250 0.550 66.350 ;
    END
  END FrameData_8
  PIN FrameData_9
    DIRECTION INPUT ;
    USE SIGNAL ;
    PORT
      LAYER MET3 ;
        RECT 0.000 66.850 0.550 66.950 ;
    END
  END FrameData_9
  PIN FrameData_10
    DIRECTION INPUT ;
    USE SIGNAL ;
    PORT
      LAYER MET3 ;
        RECT 0.000 67.450 0.550 67.550 ;
    END
  END FrameData_10
  PIN FrameData_11
    DIRECTION INPUT ;
    USE SIGNAL ;
    PORT
      LAYER MET3 ;
        RECT 0.000 68.050 0.550 68.150 ;
    END
  END FrameData_11
  PIN FrameData_12
    DIRECTION INPUT ;
    USE SIGNAL ;
    PORT
      LAYER MET3 ;
        RECT 0.000 68.650 0.550 68.750 ;
    END
  END FrameData_12
  PIN FrameData_13
    DIRECTION INPUT ;
    USE SIGNAL ;
    PORT
      LAYER MET3 ;
        RECT 0.000 69.250 0.550 69.350 ;
    END
  END FrameData_13
  PIN FrameData_14
    DIRECTION INPUT ;
    USE SIGNAL ;
    PORT
      LAYER MET3 ;
        RECT 0.000 69.850 0.550 69.950 ;
    END
  END FrameData_14
  PIN FrameData_15
    DIRECTION INPUT ;
    USE SIGNAL ;
    PORT
      LAYER MET3 ;
        RECT 0.000 70.450 0.550 70.550 ;
    END
  END FrameData_15
  PIN FrameData_16
    DIRECTION INPUT ;
    USE SIGNAL ;
    PORT
      LAYER MET3 ;
        RECT 0.000 71.050 0.550 71.150 ;
    END
  END FrameData_16
  PIN FrameData_17
    DIRECTION INPUT ;
    USE SIGNAL ;
    PORT
      LAYER MET3 ;
        RECT 0.000 71.650 0.550 71.750 ;
    END
  END FrameData_17
  PIN FrameData_18
    DIRECTION INPUT ;
    USE SIGNAL ;
    PORT
      LAYER MET3 ;
        RECT 0.000 72.250 0.550 72.350 ;
    END
  END FrameData_18
  PIN FrameData_19
    DIRECTION INPUT ;
    USE SIGNAL ;
    PORT
      LAYER MET3 ;
        RECT 0.000 72.850 0.550 72.950 ;
    END
  END FrameData_19
  PIN FrameData_20
    DIRECTION INPUT ;
    USE SIGNAL ;
    PORT
      LAYER MET3 ;
        RECT 0.000 73.450 0.550 73.550 ;
    END
  END FrameData_20
  PIN FrameData_21
    DIRECTION INPUT ;
    USE SIGNAL ;
    PORT
      LAYER MET3 ;
        RECT 0.000 74.050 0.550 74.150 ;
    END
  END FrameData_21
  PIN FrameData_22
    DIRECTION INPUT ;
    USE SIGNAL ;
    PORT
      LAYER MET3 ;
        RECT 0.000 74.650 0.550 74.750 ;
    END
  END FrameData_22
  PIN FrameData_23
    DIRECTION INPUT ;
    USE SIGNAL ;
    PORT
      LAYER MET3 ;
        RECT 0.000 75.250 0.550 75.350 ;
    END
  END FrameData_23
  PIN FrameData_24
    DIRECTION INPUT ;
    USE SIGNAL ;
    PORT
      LAYER MET3 ;
        RECT 0.000 75.850 0.550 75.950 ;
    END
  END FrameData_24
  PIN FrameData_25
    DIRECTION INPUT ;
    USE SIGNAL ;
    PORT
      LAYER MET3 ;
        RECT 0.000 76.450 0.550 76.550 ;
    END
  END FrameData_25
  PIN FrameData_26
    DIRECTION INPUT ;
    USE SIGNAL ;
    PORT
      LAYER MET3 ;
        RECT 0.000 77.050 0.550 77.150 ;
    END
  END FrameData_26
  PIN FrameData_27
    DIRECTION INPUT ;
    USE SIGNAL ;
    PORT
      LAYER MET3 ;
        RECT 0.000 77.650 0.550 77.750 ;
    END
  END FrameData_27
  PIN FrameData_28
    DIRECTION INPUT ;
    USE SIGNAL ;
    PORT
      LAYER MET3 ;
        RECT 0.000 78.250 0.550 78.350 ;
    END
  END FrameData_28
  PIN FrameData_29
    DIRECTION INPUT ;
    USE SIGNAL ;
    PORT
      LAYER MET3 ;
        RECT 0.000 78.850 0.550 78.950 ;
    END
  END FrameData_29
  PIN FrameData_30
    DIRECTION INPUT ;
    USE SIGNAL ;
    PORT
      LAYER MET3 ;
        RECT 0.000 79.450 0.550 79.550 ;
    END
  END FrameData_30
  PIN FrameData_31
    DIRECTION INPUT ;
    USE SIGNAL ;
    PORT
      LAYER MET3 ;
        RECT 0.000 80.050 0.550 80.150 ;
    END
  END FrameData_31
  PIN FrameData_O_0
    DIRECTION OUTPUT ;
    USE SIGNAL ;
    PORT
      LAYER MET3 ;
        RECT 82.050 61.450 82.600 61.550 ;
    END
  END FrameData_O_0
  PIN FrameData_O_1
    DIRECTION OUTPUT ;
    USE SIGNAL ;
    PORT
      LAYER MET3 ;
        RECT 82.050 62.050 82.600 62.150 ;
    END
  END FrameData_O_1
  PIN FrameData_O_2
    DIRECTION OUTPUT ;
    USE SIGNAL ;
    PORT
      LAYER MET3 ;
        RECT 82.050 62.650 82.600 62.750 ;
    END
  END FrameData_O_2
  PIN FrameData_O_3
    DIRECTION OUTPUT ;
    USE SIGNAL ;
    PORT
      LAYER MET3 ;
        RECT 82.050 63.250 82.600 63.350 ;
    END
  END FrameData_O_3
  PIN FrameData_O_4
    DIRECTION OUTPUT ;
    USE SIGNAL ;
    PORT
      LAYER MET3 ;
        RECT 82.050 63.850 82.600 63.950 ;
    END
  END FrameData_O_4
  PIN FrameData_O_5
    DIRECTION OUTPUT ;
    USE SIGNAL ;
    PORT
      LAYER MET3 ;
        RECT 82.050 64.450 82.600 64.550 ;
    END
  END FrameData_O_5
  PIN FrameData_O_6
    DIRECTION OUTPUT ;
    USE SIGNAL ;
    PORT
      LAYER MET3 ;
        RECT 82.050 65.050 82.600 65.150 ;
    END
  END FrameData_O_6
  PIN FrameData_O_7
    DIRECTION OUTPUT ;
    USE SIGNAL ;
    PORT
      LAYER MET3 ;
        RECT 82.050 65.650 82.600 65.750 ;
    END
  END FrameData_O_7
  PIN FrameData_O_8
    DIRECTION OUTPUT ;
    USE SIGNAL ;
    PORT
      LAYER MET3 ;
        RECT 82.050 66.250 82.600 66.350 ;
    END
  END FrameData_O_8
  PIN FrameData_O_9
    DIRECTION OUTPUT ;
    USE SIGNAL ;
    PORT
      LAYER MET3 ;
        RECT 82.050 66.850 82.600 66.950 ;
    END
  END FrameData_O_9
  PIN FrameData_O_10
    DIRECTION OUTPUT ;
    USE SIGNAL ;
    PORT
      LAYER MET3 ;
        RECT 82.050 67.450 82.600 67.550 ;
    END
  END FrameData_O_10
  PIN FrameData_O_11
    DIRECTION OUTPUT ;
    USE SIGNAL ;
    PORT
      LAYER MET3 ;
        RECT 82.050 68.050 82.600 68.150 ;
    END
  END FrameData_O_11
  PIN FrameData_O_12
    DIRECTION OUTPUT ;
    USE SIGNAL ;
    PORT
      LAYER MET3 ;
        RECT 82.050 68.650 82.600 68.750 ;
    END
  END FrameData_O_12
  PIN FrameData_O_13
    DIRECTION OUTPUT ;
    USE SIGNAL ;
    PORT
      LAYER MET3 ;
        RECT 82.050 69.250 82.600 69.350 ;
    END
  END FrameData_O_13
  PIN FrameData_O_14
    DIRECTION OUTPUT ;
    USE SIGNAL ;
    PORT
      LAYER MET3 ;
        RECT 82.050 69.850 82.600 69.950 ;
    END
  END FrameData_O_14
  PIN FrameData_O_15
    DIRECTION OUTPUT ;
    USE SIGNAL ;
    PORT
      LAYER MET3 ;
        RECT 82.050 70.450 82.600 70.550 ;
    END
  END FrameData_O_15
  PIN FrameData_O_16
    DIRECTION OUTPUT ;
    USE SIGNAL ;
    PORT
      LAYER MET3 ;
        RECT 82.050 71.050 82.600 71.150 ;
    END
  END FrameData_O_16
  PIN FrameData_O_17
    DIRECTION OUTPUT ;
    USE SIGNAL ;
    PORT
      LAYER MET3 ;
        RECT 82.050 71.650 82.600 71.750 ;
    END
  END FrameData_O_17
  PIN FrameData_O_18
    DIRECTION OUTPUT ;
    USE SIGNAL ;
    PORT
      LAYER MET3 ;
        RECT 82.050 72.250 82.600 72.350 ;
    END
  END FrameData_O_18
  PIN FrameData_O_19
    DIRECTION OUTPUT ;
    USE SIGNAL ;
    PORT
      LAYER MET3 ;
        RECT 82.050 72.850 82.600 72.950 ;
    END
  END FrameData_O_19
  PIN FrameData_O_20
    DIRECTION OUTPUT ;
    USE SIGNAL ;
    PORT
      LAYER MET3 ;
        RECT 82.050 73.450 82.600 73.550 ;
    END
  END FrameData_O_20
  PIN FrameData_O_21
    DIRECTION OUTPUT ;
    USE SIGNAL ;
    PORT
      LAYER MET3 ;
        RECT 82.050 74.050 82.600 74.150 ;
    END
  END FrameData_O_21
  PIN FrameData_O_22
    DIRECTION OUTPUT ;
    USE SIGNAL ;
    PORT
      LAYER MET3 ;
        RECT 82.050 74.650 82.600 74.750 ;
    END
  END FrameData_O_22
  PIN FrameData_O_23
    DIRECTION OUTPUT ;
    USE SIGNAL ;
    PORT
      LAYER MET3 ;
        RECT 82.050 75.250 82.600 75.350 ;
    END
  END FrameData_O_23
  PIN FrameData_O_24
    DIRECTION OUTPUT ;
    USE SIGNAL ;
    PORT
      LAYER MET3 ;
        RECT 82.050 75.850 82.600 75.950 ;
    END
  END FrameData_O_24
  PIN FrameData_O_25
    DIRECTION OUTPUT ;
    USE SIGNAL ;
    PORT
      LAYER MET3 ;
        RECT 82.050 76.450 82.600 76.550 ;
    END
  END FrameData_O_25
  PIN FrameData_O_26
    DIRECTION OUTPUT ;
    USE SIGNAL ;
    PORT
      LAYER MET3 ;
        RECT 82.050 77.050 82.600 77.150 ;
    END
  END FrameData_O_26
  PIN FrameData_O_27
    DIRECTION OUTPUT ;
    USE SIGNAL ;
    PORT
      LAYER MET3 ;
        RECT 82.050 77.650 82.600 77.750 ;
    END
  END FrameData_O_27
  PIN FrameData_O_28
    DIRECTION OUTPUT ;
    USE SIGNAL ;
    PORT
      LAYER MET3 ;
        RECT 82.050 78.250 82.600 78.350 ;
    END
  END FrameData_O_28
  PIN FrameData_O_29
    DIRECTION OUTPUT ;
    USE SIGNAL ;
    PORT
      LAYER MET3 ;
        RECT 82.050 78.850 82.600 78.950 ;
    END
  END FrameData_O_29
  PIN FrameData_O_30
    DIRECTION OUTPUT ;
    USE SIGNAL ;
    PORT
      LAYER MET3 ;
        RECT 82.050 79.450 82.600 79.550 ;
    END
  END FrameData_O_30
  PIN FrameData_O_31
    DIRECTION OUTPUT ;
    USE SIGNAL ;
    PORT
      LAYER MET3 ;
        RECT 82.050 80.050 82.600 80.150 ;
    END
  END FrameData_O_31
  PIN FrameStrobe_0
    DIRECTION INPUT ;
    USE SIGNAL ;
    PORT
      LAYER MET4 ;
        RECT 64.050 0.000 64.150 0.550 ;
    END
  END FrameStrobe_0
  PIN FrameStrobe_1
    DIRECTION INPUT ;
    USE SIGNAL ;
    PORT
      LAYER MET4 ;
        RECT 64.450 0.000 64.550 0.550 ;
    END
  END FrameStrobe_1
  PIN FrameStrobe_2
    DIRECTION INPUT ;
    USE SIGNAL ;
    PORT
      LAYER MET4 ;
        RECT 64.850 0.000 64.950 0.550 ;
    END
  END FrameStrobe_2
  PIN FrameStrobe_3
    DIRECTION INPUT ;
    USE SIGNAL ;
    PORT
      LAYER MET4 ;
        RECT 65.250 0.000 65.350 0.550 ;
    END
  END FrameStrobe_3
  PIN FrameStrobe_4
    DIRECTION INPUT ;
    USE SIGNAL ;
    PORT
      LAYER MET4 ;
        RECT 65.650 0.000 65.750 0.550 ;
    END
  END FrameStrobe_4
  PIN FrameStrobe_5
    DIRECTION INPUT ;
    USE SIGNAL ;
    PORT
      LAYER MET4 ;
        RECT 66.050 0.000 66.150 0.550 ;
    END
  END FrameStrobe_5
  PIN FrameStrobe_6
    DIRECTION INPUT ;
    USE SIGNAL ;
    PORT
      LAYER MET4 ;
        RECT 66.450 0.000 66.550 0.550 ;
    END
  END FrameStrobe_6
  PIN FrameStrobe_7
    DIRECTION INPUT ;
    USE SIGNAL ;
    PORT
      LAYER MET4 ;
        RECT 66.850 0.000 66.950 0.550 ;
    END
  END FrameStrobe_7
  PIN FrameStrobe_8
    DIRECTION INPUT ;
    USE SIGNAL ;
    PORT
      LAYER MET4 ;
        RECT 67.250 0.000 67.350 0.550 ;
    END
  END FrameStrobe_8
  PIN FrameStrobe_9
    DIRECTION INPUT ;
    USE SIGNAL ;
    PORT
      LAYER MET4 ;
        RECT 67.650 0.000 67.750 0.550 ;
    END
  END FrameStrobe_9
  PIN FrameStrobe_10
    DIRECTION INPUT ;
    USE SIGNAL ;
    PORT
      LAYER MET4 ;
        RECT 68.050 0.000 68.150 0.550 ;
    END
  END FrameStrobe_10
  PIN FrameStrobe_11
    DIRECTION INPUT ;
    USE SIGNAL ;
    PORT
      LAYER MET4 ;
        RECT 68.450 0.000 68.550 0.550 ;
    END
  END FrameStrobe_11
  PIN FrameStrobe_12
    DIRECTION INPUT ;
    USE SIGNAL ;
    PORT
      LAYER MET4 ;
        RECT 68.850 0.000 68.950 0.550 ;
    END
  END FrameStrobe_12
  PIN FrameStrobe_13
    DIRECTION INPUT ;
    USE SIGNAL ;
    PORT
      LAYER MET4 ;
        RECT 69.250 0.000 69.350 0.550 ;
    END
  END FrameStrobe_13
  PIN FrameStrobe_14
    DIRECTION INPUT ;
    USE SIGNAL ;
    PORT
      LAYER MET4 ;
        RECT 71.250 0.000 71.350 0.550 ;
    END
  END FrameStrobe_14
  PIN FrameStrobe_15
    DIRECTION INPUT ;
    USE SIGNAL ;
    PORT
      LAYER MET4 ;
        RECT 71.650 0.000 71.750 0.550 ;
    END
  END FrameStrobe_15
  PIN FrameStrobe_16
    DIRECTION INPUT ;
    USE SIGNAL ;
    PORT
      LAYER MET4 ;
        RECT 72.050 0.000 72.150 0.550 ;
    END
  END FrameStrobe_16
  PIN FrameStrobe_17
    DIRECTION INPUT ;
    USE SIGNAL ;
    PORT
      LAYER MET4 ;
        RECT 72.450 0.000 72.550 0.550 ;
    END
  END FrameStrobe_17
  PIN FrameStrobe_18
    DIRECTION INPUT ;
    USE SIGNAL ;
    PORT
      LAYER MET4 ;
        RECT 72.850 0.000 72.950 0.550 ;
    END
  END FrameStrobe_18
  PIN FrameStrobe_19
    DIRECTION INPUT ;
    USE SIGNAL ;
    PORT
      LAYER MET4 ;
        RECT 73.250 0.000 73.350 0.550 ;
    END
  END FrameStrobe_19
  PIN FrameStrobe_O_0
    DIRECTION OUTPUT ;
    USE SIGNAL ;
    PORT
      LAYER MET4 ;
        RECT 64.050 83.450 64.150 84.000 ;
    END
  END FrameStrobe_O_0
  PIN FrameStrobe_O_1
    DIRECTION OUTPUT ;
    USE SIGNAL ;
    PORT
      LAYER MET4 ;
        RECT 64.450 83.450 64.550 84.000 ;
    END
  END FrameStrobe_O_1
  PIN FrameStrobe_O_2
    DIRECTION OUTPUT ;
    USE SIGNAL ;
    PORT
      LAYER MET4 ;
        RECT 64.850 83.450 64.950 84.000 ;
    END
  END FrameStrobe_O_2
  PIN FrameStrobe_O_3
    DIRECTION OUTPUT ;
    USE SIGNAL ;
    PORT
      LAYER MET4 ;
        RECT 65.250 83.450 65.350 84.000 ;
    END
  END FrameStrobe_O_3
  PIN FrameStrobe_O_4
    DIRECTION OUTPUT ;
    USE SIGNAL ;
    PORT
      LAYER MET4 ;
        RECT 65.650 83.450 65.750 84.000 ;
    END
  END FrameStrobe_O_4
  PIN FrameStrobe_O_5
    DIRECTION OUTPUT ;
    USE SIGNAL ;
    PORT
      LAYER MET4 ;
        RECT 66.050 83.450 66.150 84.000 ;
    END
  END FrameStrobe_O_5
  PIN FrameStrobe_O_6
    DIRECTION OUTPUT ;
    USE SIGNAL ;
    PORT
      LAYER MET4 ;
        RECT 66.450 83.450 66.550 84.000 ;
    END
  END FrameStrobe_O_6
  PIN FrameStrobe_O_7
    DIRECTION OUTPUT ;
    USE SIGNAL ;
    PORT
      LAYER MET4 ;
        RECT 66.850 83.450 66.950 84.000 ;
    END
  END FrameStrobe_O_7
  PIN FrameStrobe_O_8
    DIRECTION OUTPUT ;
    USE SIGNAL ;
    PORT
      LAYER MET4 ;
        RECT 67.250 83.450 67.350 84.000 ;
    END
  END FrameStrobe_O_8
  PIN FrameStrobe_O_9
    DIRECTION OUTPUT ;
    USE SIGNAL ;
    PORT
      LAYER MET4 ;
        RECT 67.650 83.450 67.750 84.000 ;
    END
  END FrameStrobe_O_9
  PIN FrameStrobe_O_10
    DIRECTION OUTPUT ;
    USE SIGNAL ;
    PORT
      LAYER MET4 ;
        RECT 68.050 83.450 68.150 84.000 ;
    END
  END FrameStrobe_O_10
  PIN FrameStrobe_O_11
    DIRECTION OUTPUT ;
    USE SIGNAL ;
    PORT
      LAYER MET4 ;
        RECT 68.450 83.450 68.550 84.000 ;
    END
  END FrameStrobe_O_11
  PIN FrameStrobe_O_12
    DIRECTION OUTPUT ;
    USE SIGNAL ;
    PORT
      LAYER MET4 ;
        RECT 68.850 83.450 68.950 84.000 ;
    END
  END FrameStrobe_O_12
  PIN FrameStrobe_O_13
    DIRECTION OUTPUT ;
    USE SIGNAL ;
    PORT
      LAYER MET4 ;
        RECT 69.250 83.450 69.350 84.000 ;
    END
  END FrameStrobe_O_13
  PIN FrameStrobe_O_14
    DIRECTION OUTPUT ;
    USE SIGNAL ;
    PORT
      LAYER MET4 ;
        RECT 71.250 83.450 71.350 84.000 ;
    END
  END FrameStrobe_O_14
  PIN FrameStrobe_O_15
    DIRECTION OUTPUT ;
    USE SIGNAL ;
    PORT
      LAYER MET4 ;
        RECT 71.650 83.450 71.750 84.000 ;
    END
  END FrameStrobe_O_15
  PIN FrameStrobe_O_16
    DIRECTION OUTPUT ;
    USE SIGNAL ;
    PORT
      LAYER MET4 ;
        RECT 72.050 83.450 72.150 84.000 ;
    END
  END FrameStrobe_O_16
  PIN FrameStrobe_O_17
    DIRECTION OUTPUT ;
    USE SIGNAL ;
    PORT
      LAYER MET4 ;
        RECT 72.450 83.450 72.550 84.000 ;
    END
  END FrameStrobe_O_17
  PIN FrameStrobe_O_18
    DIRECTION OUTPUT ;
    USE SIGNAL ;
    PORT
      LAYER MET4 ;
        RECT 72.850 83.450 72.950 84.000 ;
    END
  END FrameStrobe_O_18
  PIN FrameStrobe_O_19
    DIRECTION OUTPUT ;
    USE SIGNAL ;
    PORT
      LAYER MET4 ;
        RECT 73.250 83.450 73.350 84.000 ;
    END
  END FrameStrobe_O_19
  PIN vdd_stripe_generate
    DIRECTION INOUT ;
    USE POWER ;
    PORT
      LAYER MET5 ;
        RECT 0.000 2.500 82.600 3.500 ;
      LAYER MET5 ;
        RECT 0.000 19.300 82.600 20.300 ;
      LAYER MET5 ;
        RECT 0.000 36.100 82.600 37.100 ;
      LAYER MET5 ;
        RECT 0.000 52.900 82.600 53.900 ;
      LAYER MET5 ;
        RECT 0.000 69.700 82.600 70.700 ;
    END
  END vdd_stripe_generate
  PIN vss_stripe_generate
    DIRECTION INOUT ;
    USE GROUND ;
    PORT
      LAYER MET5 ;
        RECT 0.000 10.900 82.600 11.900 ;
      LAYER MET5 ;
        RECT 0.000 27.700 82.600 28.700 ;
      LAYER MET5 ;
        RECT 0.000 44.500 82.600 45.500 ;
      LAYER MET5 ;
        RECT 0.000 61.300 82.600 62.300 ;
      LAYER MET5 ;
        RECT 0.000 78.100 82.600 79.100 ;
    END
  END vss_stripe_generate
  OBS
    LAYER MET1 ;
    RECT 0.000 0.000 82.600 84.000 ;
    LAYER MET2 ;
    RECT 0.000 0.000 82.600 84.000 ;
    LAYER MET3 ;
    RECT 0.000 0.000 82.600 3.750 ;
    LAYER MET3 ;
    RECT 0.650 3.750 81.950 4.050 ;
    LAYER MET3 ;
    RECT 0.000 4.050 82.600 4.350 ;
    LAYER MET3 ;
    RECT 0.650 4.350 81.950 4.650 ;
    LAYER MET3 ;
    RECT 0.000 4.650 82.600 4.950 ;
    LAYER MET3 ;
    RECT 0.650 4.950 81.950 5.250 ;
    LAYER MET3 ;
    RECT 0.000 5.250 82.600 5.550 ;
    LAYER MET3 ;
    RECT 0.650 5.550 81.950 5.850 ;
    LAYER MET3 ;
    RECT 0.000 5.850 82.600 6.150 ;
    LAYER MET3 ;
    RECT 0.650 6.150 81.950 6.450 ;
    LAYER MET3 ;
    RECT 0.000 6.450 82.600 6.750 ;
    LAYER MET3 ;
    RECT 0.650 6.750 81.950 7.050 ;
    LAYER MET3 ;
    RECT 0.000 7.050 82.600 7.350 ;
    LAYER MET3 ;
    RECT 0.650 7.350 81.950 7.650 ;
    LAYER MET3 ;
    RECT 0.000 7.650 82.600 7.950 ;
    LAYER MET3 ;
    RECT 0.650 7.950 81.950 8.250 ;
    LAYER MET3 ;
    RECT 0.000 8.250 82.600 8.550 ;
    LAYER MET3 ;
    RECT 0.650 8.550 81.950 8.850 ;
    LAYER MET3 ;
    RECT 0.000 8.850 82.600 9.150 ;
    LAYER MET3 ;
    RECT 0.650 9.150 81.950 9.450 ;
    LAYER MET3 ;
    RECT 0.000 9.450 82.600 9.750 ;
    LAYER MET3 ;
    RECT 0.650 9.750 81.950 10.050 ;
    LAYER MET3 ;
    RECT 0.000 10.050 82.600 10.350 ;
    LAYER MET3 ;
    RECT 0.650 10.350 81.950 10.650 ;
    LAYER MET3 ;
    RECT 0.000 10.650 82.600 10.950 ;
    LAYER MET3 ;
    RECT 0.650 10.950 81.950 11.250 ;
    LAYER MET3 ;
    RECT 0.000 11.250 82.600 11.550 ;
    LAYER MET3 ;
    RECT 0.650 11.550 81.950 11.850 ;
    LAYER MET3 ;
    RECT 0.000 11.850 82.600 12.150 ;
    LAYER MET3 ;
    RECT 0.650 12.150 81.950 12.450 ;
    LAYER MET3 ;
    RECT 0.000 12.450 82.600 12.750 ;
    LAYER MET3 ;
    RECT 0.650 12.750 81.950 13.050 ;
    LAYER MET3 ;
    RECT 0.000 13.050 82.600 13.350 ;
    LAYER MET3 ;
    RECT 0.650 13.350 81.950 13.650 ;
    LAYER MET3 ;
    RECT 0.000 13.650 82.600 13.950 ;
    LAYER MET3 ;
    RECT 0.650 13.950 81.950 14.250 ;
    LAYER MET3 ;
    RECT 0.000 14.250 82.600 14.550 ;
    LAYER MET3 ;
    RECT 0.650 14.550 81.950 14.850 ;
    LAYER MET3 ;
    RECT 0.000 14.850 82.600 15.150 ;
    LAYER MET3 ;
    RECT 0.650 15.150 81.950 15.450 ;
    LAYER MET3 ;
    RECT 0.000 15.450 82.600 15.750 ;
    LAYER MET3 ;
    RECT 0.650 15.750 81.950 16.050 ;
    LAYER MET3 ;
    RECT 0.000 16.050 82.600 16.350 ;
    LAYER MET3 ;
    RECT 0.650 16.350 81.950 16.650 ;
    LAYER MET3 ;
    RECT 0.000 16.650 82.600 16.950 ;
    LAYER MET3 ;
    RECT 0.650 16.950 81.950 17.250 ;
    LAYER MET3 ;
    RECT 0.000 17.250 82.600 17.550 ;
    LAYER MET3 ;
    RECT 0.650 17.550 81.950 17.850 ;
    LAYER MET3 ;
    RECT 0.000 17.850 82.600 18.150 ;
    LAYER MET3 ;
    RECT 0.650 18.150 81.950 18.450 ;
    LAYER MET3 ;
    RECT 0.000 18.450 82.600 18.750 ;
    LAYER MET3 ;
    RECT 0.650 18.750 81.950 19.050 ;
    LAYER MET3 ;
    RECT 0.000 19.050 82.600 19.350 ;
    LAYER MET3 ;
    RECT 0.650 19.350 81.950 19.650 ;
    LAYER MET3 ;
    RECT 0.000 19.650 82.600 19.950 ;
    LAYER MET3 ;
    RECT 0.650 19.950 81.950 20.250 ;
    LAYER MET3 ;
    RECT 0.000 20.250 82.600 20.550 ;
    LAYER MET3 ;
    RECT 0.650 20.550 81.950 20.850 ;
    LAYER MET3 ;
    RECT 0.000 20.850 82.600 21.150 ;
    LAYER MET3 ;
    RECT 0.650 21.150 81.950 21.450 ;
    LAYER MET3 ;
    RECT 0.000 21.450 82.600 21.750 ;
    LAYER MET3 ;
    RECT 0.650 21.750 81.950 22.050 ;
    LAYER MET3 ;
    RECT 0.000 22.050 82.600 22.350 ;
    LAYER MET3 ;
    RECT 0.650 22.350 81.950 22.650 ;
    LAYER MET3 ;
    RECT 0.000 22.650 82.600 22.950 ;
    LAYER MET3 ;
    RECT 0.650 22.950 81.950 23.250 ;
    LAYER MET3 ;
    RECT 0.000 23.250 82.600 23.550 ;
    LAYER MET3 ;
    RECT 0.650 23.550 81.950 23.850 ;
    LAYER MET3 ;
    RECT 0.000 23.850 82.600 24.150 ;
    LAYER MET3 ;
    RECT 0.650 24.150 81.950 24.450 ;
    LAYER MET3 ;
    RECT 0.000 24.450 82.600 24.750 ;
    LAYER MET3 ;
    RECT 0.650 24.750 81.950 25.050 ;
    LAYER MET3 ;
    RECT 0.000 25.050 82.600 25.350 ;
    LAYER MET3 ;
    RECT 0.650 25.350 81.950 25.650 ;
    LAYER MET3 ;
    RECT 0.000 25.650 82.600 25.950 ;
    LAYER MET3 ;
    RECT 0.650 25.950 81.950 26.250 ;
    LAYER MET3 ;
    RECT 0.000 26.250 82.600 26.550 ;
    LAYER MET3 ;
    RECT 0.650 26.550 81.950 26.850 ;
    LAYER MET3 ;
    RECT 0.000 26.850 82.600 27.150 ;
    LAYER MET3 ;
    RECT 0.650 27.150 81.950 27.450 ;
    LAYER MET3 ;
    RECT 0.000 27.450 82.600 27.750 ;
    LAYER MET3 ;
    RECT 0.650 27.750 81.950 28.050 ;
    LAYER MET3 ;
    RECT 0.000 28.050 82.600 28.350 ;
    LAYER MET3 ;
    RECT 0.650 28.350 81.950 28.650 ;
    LAYER MET3 ;
    RECT 0.000 28.650 82.600 28.950 ;
    LAYER MET3 ;
    RECT 0.650 28.950 81.950 29.250 ;
    LAYER MET3 ;
    RECT 0.000 29.250 82.600 29.550 ;
    LAYER MET3 ;
    RECT 0.650 29.550 81.950 29.850 ;
    LAYER MET3 ;
    RECT 0.000 29.850 82.600 30.150 ;
    LAYER MET3 ;
    RECT 0.650 30.150 81.950 30.450 ;
    LAYER MET3 ;
    RECT 0.000 30.450 82.600 30.750 ;
    LAYER MET3 ;
    RECT 0.650 30.750 81.950 31.050 ;
    LAYER MET3 ;
    RECT 0.000 31.050 82.600 31.350 ;
    LAYER MET3 ;
    RECT 0.650 31.350 81.950 31.650 ;
    LAYER MET3 ;
    RECT 0.000 31.650 82.600 31.950 ;
    LAYER MET3 ;
    RECT 0.650 31.950 81.950 32.250 ;
    LAYER MET3 ;
    RECT 0.000 32.250 82.600 32.550 ;
    LAYER MET3 ;
    RECT 0.650 32.550 81.950 32.850 ;
    LAYER MET3 ;
    RECT 0.000 32.850 82.600 33.150 ;
    LAYER MET3 ;
    RECT 0.650 33.150 81.950 33.450 ;
    LAYER MET3 ;
    RECT 0.000 33.450 82.600 33.750 ;
    LAYER MET3 ;
    RECT 0.650 33.750 81.950 34.050 ;
    LAYER MET3 ;
    RECT 0.000 34.050 82.600 34.350 ;
    LAYER MET3 ;
    RECT 0.650 34.350 81.950 34.650 ;
    LAYER MET3 ;
    RECT 0.000 34.650 82.600 34.950 ;
    LAYER MET3 ;
    RECT 0.650 34.950 81.950 35.250 ;
    LAYER MET3 ;
    RECT 0.000 35.250 82.600 35.550 ;
    LAYER MET3 ;
    RECT 0.650 35.550 81.950 35.850 ;
    LAYER MET3 ;
    RECT 0.000 35.850 82.600 36.150 ;
    LAYER MET3 ;
    RECT 0.650 36.150 81.950 36.450 ;
    LAYER MET3 ;
    RECT 0.000 36.450 82.600 36.750 ;
    LAYER MET3 ;
    RECT 0.650 36.750 81.950 37.050 ;
    LAYER MET3 ;
    RECT 0.000 37.050 82.600 37.350 ;
    LAYER MET3 ;
    RECT 0.650 37.350 81.950 37.650 ;
    LAYER MET3 ;
    RECT 0.000 37.650 82.600 37.950 ;
    LAYER MET3 ;
    RECT 0.650 37.950 81.950 38.250 ;
    LAYER MET3 ;
    RECT 0.000 38.250 82.600 38.550 ;
    LAYER MET3 ;
    RECT 0.650 38.550 81.950 38.850 ;
    LAYER MET3 ;
    RECT 0.000 38.850 82.600 39.150 ;
    LAYER MET3 ;
    RECT 0.650 39.150 81.950 39.450 ;
    LAYER MET3 ;
    RECT 0.000 39.450 82.600 39.750 ;
    LAYER MET3 ;
    RECT 0.650 39.750 81.950 40.050 ;
    LAYER MET3 ;
    RECT 0.000 40.050 82.600 40.350 ;
    LAYER MET3 ;
    RECT 0.650 40.350 81.950 40.650 ;
    LAYER MET3 ;
    RECT 0.000 40.650 82.600 40.950 ;
    LAYER MET3 ;
    RECT 0.650 40.950 81.950 41.250 ;
    LAYER MET3 ;
    RECT 0.000 41.250 82.600 41.550 ;
    LAYER MET3 ;
    RECT 0.650 41.550 81.950 41.850 ;
    LAYER MET3 ;
    RECT 0.000 41.850 82.600 42.150 ;
    LAYER MET3 ;
    RECT 0.650 42.150 81.950 42.450 ;
    LAYER MET3 ;
    RECT 0.000 42.450 82.600 42.750 ;
    LAYER MET3 ;
    RECT 0.650 42.750 81.950 43.050 ;
    LAYER MET3 ;
    RECT 0.000 43.050 82.600 43.350 ;
    LAYER MET3 ;
    RECT 0.650 43.350 81.950 43.650 ;
    LAYER MET3 ;
    RECT 0.000 43.650 82.600 43.950 ;
    LAYER MET3 ;
    RECT 0.650 43.950 81.950 44.250 ;
    LAYER MET3 ;
    RECT 0.000 44.250 82.600 44.550 ;
    LAYER MET3 ;
    RECT 0.650 44.550 81.950 44.850 ;
    LAYER MET3 ;
    RECT 0.000 44.850 82.600 45.150 ;
    LAYER MET3 ;
    RECT 0.650 45.150 81.950 45.450 ;
    LAYER MET3 ;
    RECT 0.000 45.450 82.600 45.750 ;
    LAYER MET3 ;
    RECT 0.650 45.750 81.950 46.050 ;
    LAYER MET3 ;
    RECT 0.000 46.050 82.600 46.350 ;
    LAYER MET3 ;
    RECT 0.650 46.350 81.950 46.650 ;
    LAYER MET3 ;
    RECT 0.000 46.650 82.600 46.950 ;
    LAYER MET3 ;
    RECT 0.650 46.950 81.950 47.250 ;
    LAYER MET3 ;
    RECT 0.000 47.250 82.600 47.550 ;
    LAYER MET3 ;
    RECT 0.650 47.550 81.950 47.850 ;
    LAYER MET3 ;
    RECT 0.000 47.850 82.600 48.150 ;
    LAYER MET3 ;
    RECT 0.650 48.150 81.950 48.450 ;
    LAYER MET3 ;
    RECT 0.000 48.450 82.600 48.750 ;
    LAYER MET3 ;
    RECT 0.650 48.750 81.950 49.050 ;
    LAYER MET3 ;
    RECT 0.000 49.050 82.600 49.350 ;
    LAYER MET3 ;
    RECT 0.650 49.350 81.950 49.650 ;
    LAYER MET3 ;
    RECT 0.000 49.650 82.600 49.950 ;
    LAYER MET3 ;
    RECT 0.650 49.950 81.950 50.250 ;
    LAYER MET3 ;
    RECT 0.000 50.250 82.600 50.550 ;
    LAYER MET3 ;
    RECT 0.650 50.550 81.950 50.850 ;
    LAYER MET3 ;
    RECT 0.000 50.850 82.600 51.150 ;
    LAYER MET3 ;
    RECT 0.650 51.150 81.950 51.450 ;
    LAYER MET3 ;
    RECT 0.000 51.450 82.600 51.750 ;
    LAYER MET3 ;
    RECT 0.650 51.750 81.950 52.050 ;
    LAYER MET3 ;
    RECT 0.000 52.050 82.600 52.350 ;
    LAYER MET3 ;
    RECT 0.650 52.350 81.950 52.650 ;
    LAYER MET3 ;
    RECT 0.000 52.650 82.600 52.950 ;
    LAYER MET3 ;
    RECT 0.650 52.950 81.950 53.250 ;
    LAYER MET3 ;
    RECT 0.000 53.250 82.600 53.550 ;
    LAYER MET3 ;
    RECT 0.650 53.550 81.950 53.850 ;
    LAYER MET3 ;
    RECT 0.000 53.850 82.600 54.150 ;
    LAYER MET3 ;
    RECT 0.650 54.150 81.950 54.450 ;
    LAYER MET3 ;
    RECT 0.000 54.450 82.600 54.750 ;
    LAYER MET3 ;
    RECT 0.650 54.750 81.950 55.050 ;
    LAYER MET3 ;
    RECT 0.000 55.050 82.600 55.350 ;
    LAYER MET3 ;
    RECT 0.650 55.350 81.950 55.650 ;
    LAYER MET3 ;
    RECT 0.000 55.650 82.600 55.950 ;
    LAYER MET3 ;
    RECT 0.650 55.950 81.950 56.250 ;
    LAYER MET3 ;
    RECT 0.000 56.250 82.600 56.550 ;
    LAYER MET3 ;
    RECT 0.650 56.550 81.950 56.850 ;
    LAYER MET3 ;
    RECT 0.000 56.850 82.600 57.150 ;
    LAYER MET3 ;
    RECT 0.650 57.150 81.950 57.450 ;
    LAYER MET3 ;
    RECT 0.000 57.450 82.600 57.750 ;
    LAYER MET3 ;
    RECT 0.650 57.750 81.950 58.050 ;
    LAYER MET3 ;
    RECT 0.000 58.050 82.600 58.350 ;
    LAYER MET3 ;
    RECT 0.650 58.350 81.950 58.650 ;
    LAYER MET3 ;
    RECT 0.000 58.650 82.600 58.950 ;
    LAYER MET3 ;
    RECT 0.650 58.950 81.950 59.250 ;
    LAYER MET3 ;
    RECT 0.000 59.250 82.600 59.550 ;
    LAYER MET3 ;
    RECT 0.650 59.550 81.950 59.850 ;
    LAYER MET3 ;
    RECT 0.000 59.850 82.600 60.150 ;
    LAYER MET3 ;
    RECT 0.650 60.150 81.950 60.450 ;
    LAYER MET3 ;
    RECT 0.000 60.450 82.600 60.750 ;
    LAYER MET3 ;
    RECT 0.650 60.750 81.950 61.050 ;
    LAYER MET3 ;
    RECT 0.000 61.050 82.600 61.350 ;
    LAYER MET3 ;
    RECT 0.650 61.350 81.950 61.650 ;
    LAYER MET3 ;
    RECT 0.000 61.650 82.600 61.950 ;
    LAYER MET3 ;
    RECT 0.650 61.950 81.950 62.250 ;
    LAYER MET3 ;
    RECT 0.000 62.250 82.600 62.550 ;
    LAYER MET3 ;
    RECT 0.650 62.550 81.950 62.850 ;
    LAYER MET3 ;
    RECT 0.000 62.850 82.600 63.150 ;
    LAYER MET3 ;
    RECT 0.650 63.150 81.950 63.450 ;
    LAYER MET3 ;
    RECT 0.000 63.450 82.600 63.750 ;
    LAYER MET3 ;
    RECT 0.650 63.750 81.950 64.050 ;
    LAYER MET3 ;
    RECT 0.000 64.050 82.600 64.350 ;
    LAYER MET3 ;
    RECT 0.650 64.350 81.950 64.650 ;
    LAYER MET3 ;
    RECT 0.000 64.650 82.600 64.950 ;
    LAYER MET3 ;
    RECT 0.650 64.950 81.950 65.250 ;
    LAYER MET3 ;
    RECT 0.000 65.250 82.600 65.550 ;
    LAYER MET3 ;
    RECT 0.650 65.550 81.950 65.850 ;
    LAYER MET3 ;
    RECT 0.000 65.850 82.600 66.150 ;
    LAYER MET3 ;
    RECT 0.650 66.150 81.950 66.450 ;
    LAYER MET3 ;
    RECT 0.000 66.450 82.600 66.750 ;
    LAYER MET3 ;
    RECT 0.650 66.750 81.950 67.050 ;
    LAYER MET3 ;
    RECT 0.000 67.050 82.600 67.350 ;
    LAYER MET3 ;
    RECT 0.650 67.350 81.950 67.650 ;
    LAYER MET3 ;
    RECT 0.000 67.650 82.600 67.950 ;
    LAYER MET3 ;
    RECT 0.650 67.950 81.950 68.250 ;
    LAYER MET3 ;
    RECT 0.000 68.250 82.600 68.550 ;
    LAYER MET3 ;
    RECT 0.650 68.550 81.950 68.850 ;
    LAYER MET3 ;
    RECT 0.000 68.850 82.600 69.150 ;
    LAYER MET3 ;
    RECT 0.650 69.150 81.950 69.450 ;
    LAYER MET3 ;
    RECT 0.000 69.450 82.600 69.750 ;
    LAYER MET3 ;
    RECT 0.650 69.750 81.950 70.050 ;
    LAYER MET3 ;
    RECT 0.000 70.050 82.600 70.350 ;
    LAYER MET3 ;
    RECT 0.650 70.350 81.950 70.650 ;
    LAYER MET3 ;
    RECT 0.000 70.650 82.600 70.950 ;
    LAYER MET3 ;
    RECT 0.650 70.950 81.950 71.250 ;
    LAYER MET3 ;
    RECT 0.000 71.250 82.600 71.550 ;
    LAYER MET3 ;
    RECT 0.650 71.550 81.950 71.850 ;
    LAYER MET3 ;
    RECT 0.000 71.850 82.600 72.150 ;
    LAYER MET3 ;
    RECT 0.650 72.150 81.950 72.450 ;
    LAYER MET3 ;
    RECT 0.000 72.450 82.600 72.750 ;
    LAYER MET3 ;
    RECT 0.650 72.750 81.950 73.050 ;
    LAYER MET3 ;
    RECT 0.000 73.050 82.600 73.350 ;
    LAYER MET3 ;
    RECT 0.650 73.350 81.950 73.650 ;
    LAYER MET3 ;
    RECT 0.000 73.650 82.600 73.950 ;
    LAYER MET3 ;
    RECT 0.650 73.950 81.950 74.250 ;
    LAYER MET3 ;
    RECT 0.000 74.250 82.600 74.550 ;
    LAYER MET3 ;
    RECT 0.650 74.550 81.950 74.850 ;
    LAYER MET3 ;
    RECT 0.000 74.850 82.600 75.150 ;
    LAYER MET3 ;
    RECT 0.650 75.150 81.950 75.450 ;
    LAYER MET3 ;
    RECT 0.000 75.450 82.600 75.750 ;
    LAYER MET3 ;
    RECT 0.650 75.750 81.950 76.050 ;
    LAYER MET3 ;
    RECT 0.000 76.050 82.600 76.350 ;
    LAYER MET3 ;
    RECT 0.650 76.350 81.950 76.650 ;
    LAYER MET3 ;
    RECT 0.000 76.650 82.600 76.950 ;
    LAYER MET3 ;
    RECT 0.650 76.950 81.950 77.250 ;
    LAYER MET3 ;
    RECT 0.000 77.250 82.600 77.550 ;
    LAYER MET3 ;
    RECT 0.650 77.550 81.950 77.850 ;
    LAYER MET3 ;
    RECT 0.000 77.850 82.600 78.150 ;
    LAYER MET3 ;
    RECT 0.650 78.150 81.950 78.450 ;
    LAYER MET3 ;
    RECT 0.000 78.450 82.600 78.750 ;
    LAYER MET3 ;
    RECT 0.650 78.750 81.950 79.050 ;
    LAYER MET3 ;
    RECT 0.000 79.050 82.600 79.350 ;
    LAYER MET3 ;
    RECT 0.650 79.350 81.950 79.650 ;
    LAYER MET3 ;
    RECT 0.000 79.650 82.600 79.950 ;
    LAYER MET3 ;
    RECT 0.650 79.950 81.950 80.250 ;
    LAYER MET3 ;
    RECT 0.000 80.250 82.600 84.000 ;
    LAYER MET4 ;
    RECT 0.000 0.000 9.150 84.000 ;
    LAYER MET4 ;
    RECT 9.150 0.650 9.450 83.350 ;
    LAYER MET4 ;
    RECT 9.450 0.000 9.550 84.000 ;
    LAYER MET4 ;
    RECT 9.550 0.650 9.850 83.350 ;
    LAYER MET4 ;
    RECT 9.850 0.000 9.950 84.000 ;
    LAYER MET4 ;
    RECT 9.950 0.650 10.250 83.350 ;
    LAYER MET4 ;
    RECT 10.250 0.000 10.350 84.000 ;
    LAYER MET4 ;
    RECT 10.350 0.650 10.650 83.350 ;
    LAYER MET4 ;
    RECT 10.650 0.000 12.350 84.000 ;
    LAYER MET4 ;
    RECT 12.350 0.650 12.650 83.350 ;
    LAYER MET4 ;
    RECT 12.650 0.000 12.750 84.000 ;
    LAYER MET4 ;
    RECT 12.750 0.650 13.050 83.350 ;
    LAYER MET4 ;
    RECT 13.050 0.000 13.150 84.000 ;
    LAYER MET4 ;
    RECT 13.150 0.650 13.450 83.350 ;
    LAYER MET4 ;
    RECT 13.450 0.000 13.550 84.000 ;
    LAYER MET4 ;
    RECT 13.550 0.650 13.850 83.350 ;
    LAYER MET4 ;
    RECT 13.850 0.000 13.950 84.000 ;
    LAYER MET4 ;
    RECT 13.950 0.650 14.250 83.350 ;
    LAYER MET4 ;
    RECT 14.250 0.000 14.350 84.000 ;
    LAYER MET4 ;
    RECT 14.350 0.650 14.650 83.350 ;
    LAYER MET4 ;
    RECT 14.650 0.000 14.750 84.000 ;
    LAYER MET4 ;
    RECT 14.750 0.650 15.050 83.350 ;
    LAYER MET4 ;
    RECT 15.050 0.000 15.150 84.000 ;
    LAYER MET4 ;
    RECT 15.150 0.650 15.450 83.350 ;
    LAYER MET4 ;
    RECT 15.450 0.000 15.550 84.000 ;
    LAYER MET4 ;
    RECT 15.550 0.650 15.850 83.350 ;
    LAYER MET4 ;
    RECT 15.850 0.000 15.950 84.000 ;
    LAYER MET4 ;
    RECT 15.950 0.650 16.250 83.350 ;
    LAYER MET4 ;
    RECT 16.250 0.000 16.350 84.000 ;
    LAYER MET4 ;
    RECT 16.350 0.650 16.650 83.350 ;
    LAYER MET4 ;
    RECT 16.650 0.000 16.750 84.000 ;
    LAYER MET4 ;
    RECT 16.750 0.650 17.050 83.350 ;
    LAYER MET4 ;
    RECT 17.050 0.000 17.150 84.000 ;
    LAYER MET4 ;
    RECT 17.150 0.650 17.450 83.350 ;
    LAYER MET4 ;
    RECT 17.450 0.000 17.550 84.000 ;
    LAYER MET4 ;
    RECT 17.550 0.650 17.850 83.350 ;
    LAYER MET4 ;
    RECT 17.850 0.000 17.950 84.000 ;
    LAYER MET4 ;
    RECT 17.950 0.650 18.250 83.350 ;
    LAYER MET4 ;
    RECT 18.250 0.000 18.350 84.000 ;
    LAYER MET4 ;
    RECT 18.350 0.650 18.650 83.350 ;
    LAYER MET4 ;
    RECT 18.650 0.000 18.750 84.000 ;
    LAYER MET4 ;
    RECT 18.750 0.650 19.050 83.350 ;
    LAYER MET4 ;
    RECT 19.050 0.000 20.750 84.000 ;
    LAYER MET4 ;
    RECT 20.750 0.650 21.050 83.350 ;
    LAYER MET4 ;
    RECT 21.050 0.000 21.150 84.000 ;
    LAYER MET4 ;
    RECT 21.150 0.650 21.450 83.350 ;
    LAYER MET4 ;
    RECT 21.450 0.000 21.550 84.000 ;
    LAYER MET4 ;
    RECT 21.550 0.650 21.850 83.350 ;
    LAYER MET4 ;
    RECT 21.850 0.000 21.950 84.000 ;
    LAYER MET4 ;
    RECT 21.950 0.650 22.250 83.350 ;
    LAYER MET4 ;
    RECT 22.250 0.000 22.350 84.000 ;
    LAYER MET4 ;
    RECT 22.350 0.650 22.650 83.350 ;
    LAYER MET4 ;
    RECT 22.650 0.000 22.750 84.000 ;
    LAYER MET4 ;
    RECT 22.750 0.650 23.050 83.350 ;
    LAYER MET4 ;
    RECT 23.050 0.000 23.150 84.000 ;
    LAYER MET4 ;
    RECT 23.150 0.650 23.450 83.350 ;
    LAYER MET4 ;
    RECT 23.450 0.000 23.550 84.000 ;
    LAYER MET4 ;
    RECT 23.550 0.650 23.850 83.350 ;
    LAYER MET4 ;
    RECT 23.850 0.000 23.950 84.000 ;
    LAYER MET4 ;
    RECT 23.950 0.650 24.250 83.350 ;
    LAYER MET4 ;
    RECT 24.250 0.000 24.350 84.000 ;
    LAYER MET4 ;
    RECT 24.350 0.650 24.650 83.350 ;
    LAYER MET4 ;
    RECT 24.650 0.000 24.750 84.000 ;
    LAYER MET4 ;
    RECT 24.750 0.650 25.050 83.350 ;
    LAYER MET4 ;
    RECT 25.050 0.000 25.150 84.000 ;
    LAYER MET4 ;
    RECT 25.150 0.650 25.450 83.350 ;
    LAYER MET4 ;
    RECT 25.450 0.000 25.550 84.000 ;
    LAYER MET4 ;
    RECT 25.550 0.650 25.850 83.350 ;
    LAYER MET4 ;
    RECT 25.850 0.000 25.950 84.000 ;
    LAYER MET4 ;
    RECT 25.950 0.650 26.250 83.350 ;
    LAYER MET4 ;
    RECT 26.250 0.000 26.350 84.000 ;
    LAYER MET4 ;
    RECT 26.350 0.650 26.650 83.350 ;
    LAYER MET4 ;
    RECT 26.650 0.000 26.750 84.000 ;
    LAYER MET4 ;
    RECT 26.750 0.650 27.050 83.350 ;
    LAYER MET4 ;
    RECT 27.050 0.000 27.150 84.000 ;
    LAYER MET4 ;
    RECT 27.150 0.650 27.450 83.350 ;
    LAYER MET4 ;
    RECT 27.450 0.000 29.150 84.000 ;
    LAYER MET4 ;
    RECT 29.150 0.650 29.450 83.350 ;
    LAYER MET4 ;
    RECT 29.450 0.000 29.550 84.000 ;
    LAYER MET4 ;
    RECT 29.550 0.650 29.850 83.350 ;
    LAYER MET4 ;
    RECT 29.850 0.000 29.950 84.000 ;
    LAYER MET4 ;
    RECT 29.950 0.650 30.250 83.350 ;
    LAYER MET4 ;
    RECT 30.250 0.000 30.350 84.000 ;
    LAYER MET4 ;
    RECT 30.350 0.650 30.650 83.350 ;
    LAYER MET4 ;
    RECT 30.650 0.000 30.750 84.000 ;
    LAYER MET4 ;
    RECT 30.750 0.650 31.050 83.350 ;
    LAYER MET4 ;
    RECT 31.050 0.000 31.150 84.000 ;
    LAYER MET4 ;
    RECT 31.150 0.650 31.450 83.350 ;
    LAYER MET4 ;
    RECT 31.450 0.000 31.550 84.000 ;
    LAYER MET4 ;
    RECT 31.550 0.650 31.850 83.350 ;
    LAYER MET4 ;
    RECT 31.850 0.000 31.950 84.000 ;
    LAYER MET4 ;
    RECT 31.950 0.650 32.250 83.350 ;
    LAYER MET4 ;
    RECT 32.250 0.000 32.350 84.000 ;
    LAYER MET4 ;
    RECT 32.350 0.650 32.650 83.350 ;
    LAYER MET4 ;
    RECT 32.650 0.000 32.750 84.000 ;
    LAYER MET4 ;
    RECT 32.750 0.650 33.050 83.350 ;
    LAYER MET4 ;
    RECT 33.050 0.000 33.150 84.000 ;
    LAYER MET4 ;
    RECT 33.150 0.650 33.450 83.350 ;
    LAYER MET4 ;
    RECT 33.450 0.000 33.550 84.000 ;
    LAYER MET4 ;
    RECT 33.550 0.650 33.850 83.350 ;
    LAYER MET4 ;
    RECT 33.850 0.000 33.950 84.000 ;
    LAYER MET4 ;
    RECT 33.950 0.650 34.250 83.350 ;
    LAYER MET4 ;
    RECT 34.250 0.000 34.350 84.000 ;
    LAYER MET4 ;
    RECT 34.350 0.650 34.650 83.350 ;
    LAYER MET4 ;
    RECT 34.650 0.000 34.750 84.000 ;
    LAYER MET4 ;
    RECT 34.750 0.650 35.050 83.350 ;
    LAYER MET4 ;
    RECT 35.050 0.000 35.150 84.000 ;
    LAYER MET4 ;
    RECT 35.150 0.650 35.450 83.350 ;
    LAYER MET4 ;
    RECT 35.450 0.000 35.550 84.000 ;
    LAYER MET4 ;
    RECT 35.550 0.650 35.850 83.350 ;
    LAYER MET4 ;
    RECT 35.850 0.000 37.550 84.000 ;
    LAYER MET4 ;
    RECT 37.550 0.650 37.850 83.350 ;
    LAYER MET4 ;
    RECT 37.850 0.000 37.950 84.000 ;
    LAYER MET4 ;
    RECT 37.950 0.650 38.250 83.350 ;
    LAYER MET4 ;
    RECT 38.250 0.000 38.350 84.000 ;
    LAYER MET4 ;
    RECT 38.350 0.650 38.650 83.350 ;
    LAYER MET4 ;
    RECT 38.650 0.000 38.750 84.000 ;
    LAYER MET4 ;
    RECT 38.750 0.650 39.050 83.350 ;
    LAYER MET4 ;
    RECT 39.050 0.000 39.150 84.000 ;
    LAYER MET4 ;
    RECT 39.150 0.650 39.450 83.350 ;
    LAYER MET4 ;
    RECT 39.450 0.000 39.550 84.000 ;
    LAYER MET4 ;
    RECT 39.550 0.650 39.850 83.350 ;
    LAYER MET4 ;
    RECT 39.850 0.000 39.950 84.000 ;
    LAYER MET4 ;
    RECT 39.950 0.650 40.250 83.350 ;
    LAYER MET4 ;
    RECT 40.250 0.000 40.350 84.000 ;
    LAYER MET4 ;
    RECT 40.350 0.650 40.650 83.350 ;
    LAYER MET4 ;
    RECT 40.650 0.000 40.750 84.000 ;
    LAYER MET4 ;
    RECT 40.750 0.650 41.050 83.350 ;
    LAYER MET4 ;
    RECT 41.050 0.000 41.150 84.000 ;
    LAYER MET4 ;
    RECT 41.150 0.650 41.450 83.350 ;
    LAYER MET4 ;
    RECT 41.450 0.000 41.550 84.000 ;
    LAYER MET4 ;
    RECT 41.550 0.650 41.850 83.350 ;
    LAYER MET4 ;
    RECT 41.850 0.000 41.950 84.000 ;
    LAYER MET4 ;
    RECT 41.950 0.650 42.250 83.350 ;
    LAYER MET4 ;
    RECT 42.250 0.000 42.350 84.000 ;
    LAYER MET4 ;
    RECT 42.350 0.650 42.650 83.350 ;
    LAYER MET4 ;
    RECT 42.650 0.000 42.750 84.000 ;
    LAYER MET4 ;
    RECT 42.750 0.650 43.050 83.350 ;
    LAYER MET4 ;
    RECT 43.050 0.000 43.150 84.000 ;
    LAYER MET4 ;
    RECT 43.150 0.650 43.450 83.350 ;
    LAYER MET4 ;
    RECT 43.450 0.000 43.550 84.000 ;
    LAYER MET4 ;
    RECT 43.550 0.650 43.850 83.350 ;
    LAYER MET4 ;
    RECT 43.850 0.000 43.950 84.000 ;
    LAYER MET4 ;
    RECT 43.950 0.650 44.250 83.350 ;
    LAYER MET4 ;
    RECT 44.250 0.000 45.950 84.000 ;
    LAYER MET4 ;
    RECT 45.950 0.650 46.250 83.350 ;
    LAYER MET4 ;
    RECT 46.250 0.000 46.350 84.000 ;
    LAYER MET4 ;
    RECT 46.350 0.650 46.650 83.350 ;
    LAYER MET4 ;
    RECT 46.650 0.000 46.750 84.000 ;
    LAYER MET4 ;
    RECT 46.750 0.650 47.050 83.350 ;
    LAYER MET4 ;
    RECT 47.050 0.000 47.150 84.000 ;
    LAYER MET4 ;
    RECT 47.150 0.650 47.450 83.350 ;
    LAYER MET4 ;
    RECT 47.450 0.000 47.550 84.000 ;
    LAYER MET4 ;
    RECT 47.550 0.650 47.850 83.350 ;
    LAYER MET4 ;
    RECT 47.850 0.000 47.950 84.000 ;
    LAYER MET4 ;
    RECT 47.950 0.650 48.250 83.350 ;
    LAYER MET4 ;
    RECT 48.250 0.000 48.350 84.000 ;
    LAYER MET4 ;
    RECT 48.350 0.650 48.650 83.350 ;
    LAYER MET4 ;
    RECT 48.650 0.000 48.750 84.000 ;
    LAYER MET4 ;
    RECT 48.750 0.650 49.050 83.350 ;
    LAYER MET4 ;
    RECT 49.050 0.000 49.150 84.000 ;
    LAYER MET4 ;
    RECT 49.150 0.650 49.450 83.350 ;
    LAYER MET4 ;
    RECT 49.450 0.000 49.550 84.000 ;
    LAYER MET4 ;
    RECT 49.550 0.650 49.850 83.350 ;
    LAYER MET4 ;
    RECT 49.850 0.000 49.950 84.000 ;
    LAYER MET4 ;
    RECT 49.950 0.650 50.250 83.350 ;
    LAYER MET4 ;
    RECT 50.250 0.000 50.350 84.000 ;
    LAYER MET4 ;
    RECT 50.350 0.650 50.650 83.350 ;
    LAYER MET4 ;
    RECT 50.650 0.000 50.750 84.000 ;
    LAYER MET4 ;
    RECT 50.750 0.650 51.050 83.350 ;
    LAYER MET4 ;
    RECT 51.050 0.000 51.150 84.000 ;
    LAYER MET4 ;
    RECT 51.150 0.650 51.450 83.350 ;
    LAYER MET4 ;
    RECT 51.450 0.000 51.550 84.000 ;
    LAYER MET4 ;
    RECT 51.550 0.650 51.850 83.350 ;
    LAYER MET4 ;
    RECT 51.850 0.000 51.950 84.000 ;
    LAYER MET4 ;
    RECT 51.950 0.650 52.250 83.350 ;
    LAYER MET4 ;
    RECT 52.250 0.000 52.350 84.000 ;
    LAYER MET4 ;
    RECT 52.350 0.650 52.650 83.350 ;
    LAYER MET4 ;
    RECT 52.650 0.000 54.350 84.000 ;
    LAYER MET4 ;
    RECT 54.350 0.650 54.650 83.350 ;
    LAYER MET4 ;
    RECT 54.650 0.000 54.750 84.000 ;
    LAYER MET4 ;
    RECT 54.750 0.650 55.050 83.350 ;
    LAYER MET4 ;
    RECT 55.050 0.000 55.150 84.000 ;
    LAYER MET4 ;
    RECT 55.150 0.650 55.450 83.350 ;
    LAYER MET4 ;
    RECT 55.450 0.000 55.550 84.000 ;
    LAYER MET4 ;
    RECT 55.550 0.650 55.850 83.350 ;
    LAYER MET4 ;
    RECT 55.850 0.000 55.950 84.000 ;
    LAYER MET4 ;
    RECT 55.950 0.650 56.250 83.350 ;
    LAYER MET4 ;
    RECT 56.250 0.000 56.350 84.000 ;
    LAYER MET4 ;
    RECT 56.350 0.650 56.650 83.350 ;
    LAYER MET4 ;
    RECT 56.650 0.000 56.750 84.000 ;
    LAYER MET4 ;
    RECT 56.750 0.650 57.050 83.350 ;
    LAYER MET4 ;
    RECT 57.050 0.000 57.150 84.000 ;
    LAYER MET4 ;
    RECT 57.150 0.650 57.450 83.350 ;
    LAYER MET4 ;
    RECT 57.450 0.000 57.550 84.000 ;
    LAYER MET4 ;
    RECT 57.550 0.650 57.850 83.350 ;
    LAYER MET4 ;
    RECT 57.850 0.000 57.950 84.000 ;
    LAYER MET4 ;
    RECT 57.950 0.650 58.250 83.350 ;
    LAYER MET4 ;
    RECT 58.250 0.000 58.350 84.000 ;
    LAYER MET4 ;
    RECT 58.350 0.650 58.650 83.350 ;
    LAYER MET4 ;
    RECT 58.650 0.000 58.750 84.000 ;
    LAYER MET4 ;
    RECT 58.750 0.650 59.050 83.350 ;
    LAYER MET4 ;
    RECT 59.050 0.000 59.150 84.000 ;
    LAYER MET4 ;
    RECT 59.150 0.650 59.450 83.350 ;
    LAYER MET4 ;
    RECT 59.450 0.000 59.550 84.000 ;
    LAYER MET4 ;
    RECT 59.550 0.650 59.850 83.350 ;
    LAYER MET4 ;
    RECT 59.850 0.000 59.950 84.000 ;
    LAYER MET4 ;
    RECT 59.950 0.650 60.250 83.350 ;
    LAYER MET4 ;
    RECT 60.250 0.000 60.350 84.000 ;
    LAYER MET4 ;
    RECT 60.350 0.650 60.650 83.350 ;
    LAYER MET4 ;
    RECT 60.650 0.000 60.750 84.000 ;
    LAYER MET4 ;
    RECT 60.750 0.650 61.050 83.350 ;
    LAYER MET4 ;
    RECT 61.050 0.000 62.750 84.000 ;
    LAYER MET4 ;
    RECT 62.750 0.650 63.050 83.350 ;
    LAYER MET4 ;
    RECT 63.050 0.000 63.150 84.000 ;
    LAYER MET4 ;
    RECT 63.150 0.650 63.450 83.350 ;
    LAYER MET4 ;
    RECT 63.450 0.000 63.550 84.000 ;
    LAYER MET4 ;
    RECT 63.550 0.650 63.850 83.350 ;
    LAYER MET4 ;
    RECT 63.850 0.000 63.950 84.000 ;
    LAYER MET4 ;
    RECT 63.950 0.650 64.250 83.350 ;
    LAYER MET4 ;
    RECT 64.250 0.000 64.350 84.000 ;
    LAYER MET4 ;
    RECT 64.350 0.650 64.650 83.350 ;
    LAYER MET4 ;
    RECT 64.650 0.000 64.750 84.000 ;
    LAYER MET4 ;
    RECT 64.750 0.650 65.050 83.350 ;
    LAYER MET4 ;
    RECT 65.050 0.000 65.150 84.000 ;
    LAYER MET4 ;
    RECT 65.150 0.650 65.450 83.350 ;
    LAYER MET4 ;
    RECT 65.450 0.000 65.550 84.000 ;
    LAYER MET4 ;
    RECT 65.550 0.650 65.850 83.350 ;
    LAYER MET4 ;
    RECT 65.850 0.000 65.950 84.000 ;
    LAYER MET4 ;
    RECT 65.950 0.650 66.250 83.350 ;
    LAYER MET4 ;
    RECT 66.250 0.000 66.350 84.000 ;
    LAYER MET4 ;
    RECT 66.350 0.650 66.650 83.350 ;
    LAYER MET4 ;
    RECT 66.650 0.000 66.750 84.000 ;
    LAYER MET4 ;
    RECT 66.750 0.650 67.050 83.350 ;
    LAYER MET4 ;
    RECT 67.050 0.000 67.150 84.000 ;
    LAYER MET4 ;
    RECT 67.150 0.650 67.450 83.350 ;
    LAYER MET4 ;
    RECT 67.450 0.000 67.550 84.000 ;
    LAYER MET4 ;
    RECT 67.550 0.650 67.850 83.350 ;
    LAYER MET4 ;
    RECT 67.850 0.000 67.950 84.000 ;
    LAYER MET4 ;
    RECT 67.950 0.650 68.250 83.350 ;
    LAYER MET4 ;
    RECT 68.250 0.000 68.350 84.000 ;
    LAYER MET4 ;
    RECT 68.350 0.650 68.650 83.350 ;
    LAYER MET4 ;
    RECT 68.650 0.000 68.750 84.000 ;
    LAYER MET4 ;
    RECT 68.750 0.650 69.050 83.350 ;
    LAYER MET4 ;
    RECT 69.050 0.000 69.150 84.000 ;
    LAYER MET4 ;
    RECT 69.150 0.650 69.450 83.350 ;
    LAYER MET4 ;
    RECT 69.450 0.000 71.150 84.000 ;
    LAYER MET4 ;
    RECT 71.150 0.650 71.450 83.350 ;
    LAYER MET4 ;
    RECT 71.450 0.000 71.550 84.000 ;
    LAYER MET4 ;
    RECT 71.550 0.650 71.850 83.350 ;
    LAYER MET4 ;
    RECT 71.850 0.000 71.950 84.000 ;
    LAYER MET4 ;
    RECT 71.950 0.650 72.250 83.350 ;
    LAYER MET4 ;
    RECT 72.250 0.000 72.350 84.000 ;
    LAYER MET4 ;
    RECT 72.350 0.650 72.650 83.350 ;
    LAYER MET4 ;
    RECT 72.650 0.000 72.750 84.000 ;
    LAYER MET4 ;
    RECT 72.750 0.650 73.050 83.350 ;
    LAYER MET4 ;
    RECT 73.050 0.000 73.150 84.000 ;
    LAYER MET4 ;
    RECT 73.150 0.650 73.450 83.350 ;
    LAYER MET4 ;
    RECT 73.450 0.000 82.600 84.000 ;
    LAYER MET5 ;
    RECT 0.000 0.000 82.600 2.400 ;
    LAYER MET5 ;
    RECT 0.000 3.600 82.600 10.800 ;
    LAYER MET5 ;
    RECT 0.000 12.000 82.600 19.200 ;
    LAYER MET5 ;
    RECT 0.000 20.400 82.600 27.600 ;
    LAYER MET5 ;
    RECT 0.000 28.800 82.600 36.000 ;
    LAYER MET5 ;
    RECT 0.000 37.200 82.600 44.400 ;
    LAYER MET5 ;
    RECT 0.000 45.600 82.600 52.800 ;
    LAYER MET5 ;
    RECT 0.000 54.000 82.600 61.200 ;
    LAYER MET5 ;
    RECT 0.000 62.400 82.600 69.600 ;
    LAYER MET5 ;
    RECT 0.000 70.800 82.600 78.000 ;
    LAYER MET5 ;
    RECT 0.000 79.200 82.600 84.000 ;
  END

END LUT4x8_ha

END LIBRARY
